VERSION 5.8 ;
BUSBITCHARS "[]" ;
DIVIDERCHAR "/" ;
UNITS
    DATABASE MICRONS 1000 ;
END UNITS

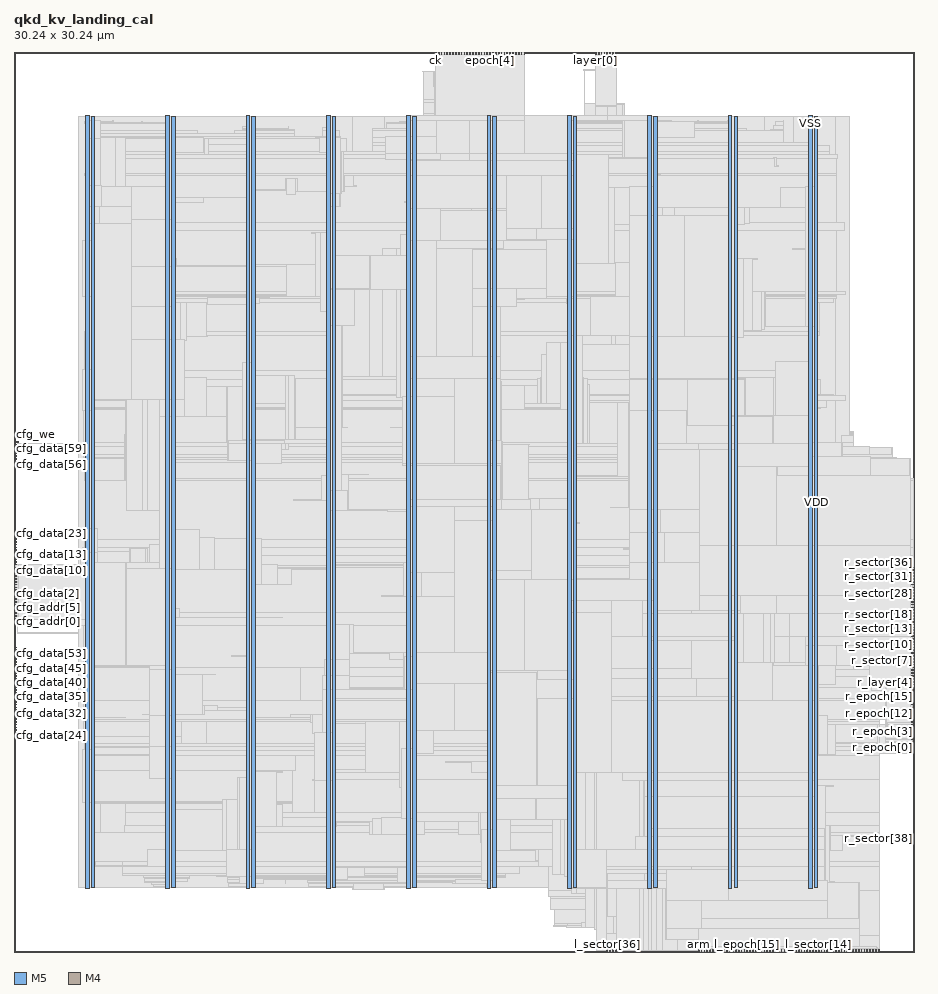
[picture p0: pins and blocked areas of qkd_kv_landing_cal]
MACRO qkd_kv_landing_cal
  FOREIGN qkd_kv_landing_cal 0 0 ;
  CLASS BLOCK ;
  SIZE 30.24 BY 30.24 ;
  PIN arm
    DIRECTION OUTPUT ;
    USE SIGNAL ;
    PORT
      LAYER M5 ;
        RECT  22.992 0 23.016 0.084 ;
    END
  END arm
  PIN cfg_addr[0]
    DIRECTION INPUT ;
    USE SIGNAL ;
    PORT
      LAYER M4 ;
        RECT  0 11.088 0.084 11.112 ;
    END
  END cfg_addr[0]
  PIN cfg_addr[1]
    DIRECTION INPUT ;
    USE SIGNAL ;
    PORT
      LAYER M4 ;
        RECT  0 11.184 0.084 11.208 ;
    END
  END cfg_addr[1]
  PIN cfg_addr[2]
    DIRECTION INPUT ;
    USE SIGNAL ;
    PORT
      LAYER M4 ;
        RECT  0 11.28 0.084 11.304 ;
    END
  END cfg_addr[2]
  PIN cfg_addr[3]
    DIRECTION INPUT ;
    USE SIGNAL ;
    PORT
      LAYER M4 ;
        RECT  0 11.376 0.084 11.4 ;
    END
  END cfg_addr[3]
  PIN cfg_addr[4]
    DIRECTION INPUT ;
    USE SIGNAL ;
    PORT
      LAYER M4 ;
        RECT  0 11.472 0.084 11.496 ;
    END
  END cfg_addr[4]
  PIN cfg_addr[5]
    DIRECTION INPUT ;
    USE SIGNAL ;
    PORT
      LAYER M4 ;
        RECT  0 11.568 0.084 11.592 ;
    END
  END cfg_addr[5]
  PIN cfg_addr[6]
    DIRECTION INPUT ;
    USE SIGNAL ;
    PORT
      LAYER M4 ;
        RECT  0 11.664 0.084 11.688 ;
    END
  END cfg_addr[6]
  PIN cfg_addr[7]
    DIRECTION INPUT ;
    USE SIGNAL ;
    PORT
      LAYER M4 ;
        RECT  0 11.76 0.084 11.784 ;
    END
  END cfg_addr[7]
  PIN cfg_data[0]
    DIRECTION INPUT ;
    USE SIGNAL ;
    PORT
      LAYER M4 ;
        RECT  0 11.856 0.084 11.88 ;
    END
  END cfg_data[0]
  PIN cfg_data[10]
    DIRECTION INPUT ;
    USE SIGNAL ;
    PORT
      LAYER M4 ;
        RECT  0 12.816 0.084 12.84 ;
    END
  END cfg_data[10]
  PIN cfg_data[11]
    DIRECTION INPUT ;
    USE SIGNAL ;
    PORT
      LAYER M4 ;
        RECT  0 12.912 0.084 12.936 ;
    END
  END cfg_data[11]
  PIN cfg_data[12]
    DIRECTION INPUT ;
    USE SIGNAL ;
    PORT
      LAYER M4 ;
        RECT  0 13.008 0.084 13.032 ;
    END
  END cfg_data[12]
  PIN cfg_data[13]
    DIRECTION INPUT ;
    USE SIGNAL ;
    PORT
      LAYER M4 ;
        RECT  0 13.104 0.084 13.128 ;
    END
  END cfg_data[13]
  PIN cfg_data[14]
    DIRECTION INPUT ;
    USE SIGNAL ;
    PORT
      LAYER M4 ;
        RECT  0 13.2 0.084 13.224 ;
    END
  END cfg_data[14]
  PIN cfg_data[15]
    DIRECTION INPUT ;
    USE SIGNAL ;
    PORT
      LAYER M4 ;
        RECT  0 13.296 0.084 13.32 ;
    END
  END cfg_data[15]
  PIN cfg_data[16]
    DIRECTION INPUT ;
    USE SIGNAL ;
    PORT
      LAYER M4 ;
        RECT  0 13.392 0.084 13.416 ;
    END
  END cfg_data[16]
  PIN cfg_data[17]
    DIRECTION INPUT ;
    USE SIGNAL ;
    PORT
      LAYER M4 ;
        RECT  0 13.488 0.084 13.512 ;
    END
  END cfg_data[17]
  PIN cfg_data[18]
    DIRECTION INPUT ;
    USE SIGNAL ;
    PORT
      LAYER M4 ;
        RECT  0 13.584 0.084 13.608 ;
    END
  END cfg_data[18]
  PIN cfg_data[19]
    DIRECTION INPUT ;
    USE SIGNAL ;
    PORT
      LAYER M4 ;
        RECT  0 13.68 0.084 13.704 ;
    END
  END cfg_data[19]
  PIN cfg_data[1]
    DIRECTION INPUT ;
    USE SIGNAL ;
    PORT
      LAYER M4 ;
        RECT  0 11.952 0.084 11.976 ;
    END
  END cfg_data[1]
  PIN cfg_data[20]
    DIRECTION INPUT ;
    USE SIGNAL ;
    PORT
      LAYER M4 ;
        RECT  0 13.776 0.084 13.8 ;
    END
  END cfg_data[20]
  PIN cfg_data[21]
    DIRECTION INPUT ;
    USE SIGNAL ;
    PORT
      LAYER M4 ;
        RECT  0 13.872 0.084 13.896 ;
    END
  END cfg_data[21]
  PIN cfg_data[22]
    DIRECTION INPUT ;
    USE SIGNAL ;
    PORT
      LAYER M4 ;
        RECT  0 13.968 0.084 13.992 ;
    END
  END cfg_data[22]
  PIN cfg_data[23]
    DIRECTION INPUT ;
    USE SIGNAL ;
    PORT
      LAYER M4 ;
        RECT  0 14.064 0.084 14.088 ;
    END
  END cfg_data[23]
  PIN cfg_data[24]
    DIRECTION INPUT ;
    USE SIGNAL ;
    PORT
      LAYER M4 ;
        RECT  0 7.248 0.084 7.272 ;
    END
  END cfg_data[24]
  PIN cfg_data[25]
    DIRECTION INPUT ;
    USE SIGNAL ;
    PORT
      LAYER M4 ;
        RECT  0 7.344 0.084 7.368 ;
    END
  END cfg_data[25]
  PIN cfg_data[26]
    DIRECTION INPUT ;
    USE SIGNAL ;
    PORT
      LAYER M4 ;
        RECT  0 7.44 0.084 7.464 ;
    END
  END cfg_data[26]
  PIN cfg_data[27]
    DIRECTION INPUT ;
    USE SIGNAL ;
    PORT
      LAYER M4 ;
        RECT  0 7.536 0.084 7.56 ;
    END
  END cfg_data[27]
  PIN cfg_data[28]
    DIRECTION INPUT ;
    USE SIGNAL ;
    PORT
      LAYER M4 ;
        RECT  0 7.632 0.084 7.656 ;
    END
  END cfg_data[28]
  PIN cfg_data[29]
    DIRECTION INPUT ;
    USE SIGNAL ;
    PORT
      LAYER M4 ;
        RECT  0 7.728 0.084 7.752 ;
    END
  END cfg_data[29]
  PIN cfg_data[2]
    DIRECTION INPUT ;
    USE SIGNAL ;
    PORT
      LAYER M4 ;
        RECT  0 12.048 0.084 12.072 ;
    END
  END cfg_data[2]
  PIN cfg_data[30]
    DIRECTION INPUT ;
    USE SIGNAL ;
    PORT
      LAYER M4 ;
        RECT  0 7.824 0.084 7.848 ;
    END
  END cfg_data[30]
  PIN cfg_data[31]
    DIRECTION INPUT ;
    USE SIGNAL ;
    PORT
      LAYER M4 ;
        RECT  0 7.92 0.084 7.944 ;
    END
  END cfg_data[31]
  PIN cfg_data[32]
    DIRECTION INPUT ;
    USE SIGNAL ;
    PORT
      LAYER M4 ;
        RECT  0 8.016 0.084 8.04 ;
    END
  END cfg_data[32]
  PIN cfg_data[33]
    DIRECTION INPUT ;
    USE SIGNAL ;
    PORT
      LAYER M4 ;
        RECT  0 8.112 0.084 8.136 ;
    END
  END cfg_data[33]
  PIN cfg_data[34]
    DIRECTION INPUT ;
    USE SIGNAL ;
    PORT
      LAYER M4 ;
        RECT  0 8.208 0.084 8.232 ;
    END
  END cfg_data[34]
  PIN cfg_data[35]
    DIRECTION INPUT ;
    USE SIGNAL ;
    PORT
      LAYER M4 ;
        RECT  0 8.304 0.084 8.328 ;
    END
  END cfg_data[35]
  PIN cfg_data[36]
    DIRECTION INPUT ;
    USE SIGNAL ;
    PORT
      LAYER M4 ;
        RECT  0 8.4 0.084 8.424 ;
    END
  END cfg_data[36]
  PIN cfg_data[37]
    DIRECTION INPUT ;
    USE SIGNAL ;
    PORT
      LAYER M4 ;
        RECT  0 8.496 0.084 8.52 ;
    END
  END cfg_data[37]
  PIN cfg_data[38]
    DIRECTION INPUT ;
    USE SIGNAL ;
    PORT
      LAYER M4 ;
        RECT  0 8.592 0.084 8.616 ;
    END
  END cfg_data[38]
  PIN cfg_data[39]
    DIRECTION INPUT ;
    USE SIGNAL ;
    PORT
      LAYER M4 ;
        RECT  0 8.688 0.084 8.712 ;
    END
  END cfg_data[39]
  PIN cfg_data[3]
    DIRECTION INPUT ;
    USE SIGNAL ;
    PORT
      LAYER M4 ;
        RECT  0 12.144 0.084 12.168 ;
    END
  END cfg_data[3]
  PIN cfg_data[40]
    DIRECTION INPUT ;
    USE SIGNAL ;
    PORT
      LAYER M4 ;
        RECT  0 8.784 0.084 8.808 ;
    END
  END cfg_data[40]
  PIN cfg_data[41]
    DIRECTION INPUT ;
    USE SIGNAL ;
    PORT
      LAYER M4 ;
        RECT  0 8.88 0.084 8.904 ;
    END
  END cfg_data[41]
  PIN cfg_data[42]
    DIRECTION INPUT ;
    USE SIGNAL ;
    PORT
      LAYER M4 ;
        RECT  0 8.976 0.084 9 ;
    END
  END cfg_data[42]
  PIN cfg_data[43]
    DIRECTION INPUT ;
    USE SIGNAL ;
    PORT
      LAYER M4 ;
        RECT  0 9.072 0.084 9.096 ;
    END
  END cfg_data[43]
  PIN cfg_data[44]
    DIRECTION INPUT ;
    USE SIGNAL ;
    PORT
      LAYER M4 ;
        RECT  0 9.168 0.084 9.192 ;
    END
  END cfg_data[44]
  PIN cfg_data[45]
    DIRECTION INPUT ;
    USE SIGNAL ;
    PORT
      LAYER M4 ;
        RECT  0 9.264 0.084 9.288 ;
    END
  END cfg_data[45]
  PIN cfg_data[46]
    DIRECTION INPUT ;
    USE SIGNAL ;
    PORT
      LAYER M4 ;
        RECT  0 9.36 0.084 9.384 ;
    END
  END cfg_data[46]
  PIN cfg_data[47]
    DIRECTION INPUT ;
    USE SIGNAL ;
    PORT
      LAYER M4 ;
        RECT  0 9.456 0.084 9.48 ;
    END
  END cfg_data[47]
  PIN cfg_data[48]
    DIRECTION INPUT ;
    USE SIGNAL ;
    PORT
      LAYER M4 ;
        RECT  0 9.552 0.084 9.576 ;
    END
  END cfg_data[48]
  PIN cfg_data[49]
    DIRECTION INPUT ;
    USE SIGNAL ;
    PORT
      LAYER M4 ;
        RECT  0 9.648 0.084 9.672 ;
    END
  END cfg_data[49]
  PIN cfg_data[4]
    DIRECTION INPUT ;
    USE SIGNAL ;
    PORT
      LAYER M4 ;
        RECT  0 12.24 0.084 12.264 ;
    END
  END cfg_data[4]
  PIN cfg_data[50]
    DIRECTION INPUT ;
    USE SIGNAL ;
    PORT
      LAYER M4 ;
        RECT  0 9.744 0.084 9.768 ;
    END
  END cfg_data[50]
  PIN cfg_data[51]
    DIRECTION INPUT ;
    USE SIGNAL ;
    PORT
      LAYER M4 ;
        RECT  0 9.84 0.084 9.864 ;
    END
  END cfg_data[51]
  PIN cfg_data[52]
    DIRECTION INPUT ;
    USE SIGNAL ;
    PORT
      LAYER M4 ;
        RECT  0 9.936 0.084 9.96 ;
    END
  END cfg_data[52]
  PIN cfg_data[53]
    DIRECTION INPUT ;
    USE SIGNAL ;
    PORT
      LAYER M4 ;
        RECT  0 10.032 0.084 10.056 ;
    END
  END cfg_data[53]
  PIN cfg_data[54]
    DIRECTION INPUT ;
    USE SIGNAL ;
    PORT
      LAYER M4 ;
        RECT  0 10.128 0.084 10.152 ;
    END
  END cfg_data[54]
  PIN cfg_data[55]
    DIRECTION INPUT ;
    USE SIGNAL ;
    PORT
      LAYER M4 ;
        RECT  0 10.224 0.084 10.248 ;
    END
  END cfg_data[55]
  PIN cfg_data[56]
    DIRECTION INPUT ;
    USE SIGNAL ;
    PORT
      LAYER M4 ;
        RECT  0 16.368 0.084 16.392 ;
    END
  END cfg_data[56]
  PIN cfg_data[57]
    DIRECTION INPUT ;
    USE SIGNAL ;
    PORT
      LAYER M4 ;
        RECT  0 16.464 0.084 16.488 ;
    END
  END cfg_data[57]
  PIN cfg_data[58]
    DIRECTION INPUT ;
    USE SIGNAL ;
    PORT
      LAYER M4 ;
        RECT  0 16.56 0.084 16.584 ;
    END
  END cfg_data[58]
  PIN cfg_data[59]
    DIRECTION INPUT ;
    USE SIGNAL ;
    PORT
      LAYER M4 ;
        RECT  0 16.656 0.084 16.68 ;
    END
  END cfg_data[59]
  PIN cfg_data[5]
    DIRECTION INPUT ;
    USE SIGNAL ;
    PORT
      LAYER M4 ;
        RECT  0 12.336 0.084 12.36 ;
    END
  END cfg_data[5]
  PIN cfg_data[60]
    DIRECTION INPUT ;
    USE SIGNAL ;
    PORT
      LAYER M4 ;
        RECT  0 16.752 0.084 16.776 ;
    END
  END cfg_data[60]
  PIN cfg_data[61]
    DIRECTION INPUT ;
    USE SIGNAL ;
    PORT
      LAYER M4 ;
        RECT  0 16.848 0.084 16.872 ;
    END
  END cfg_data[61]
  PIN cfg_data[62]
    DIRECTION INPUT ;
    USE SIGNAL ;
    PORT
      LAYER M4 ;
        RECT  0 16.944 0.084 16.968 ;
    END
  END cfg_data[62]
  PIN cfg_data[63]
    DIRECTION INPUT ;
    USE SIGNAL ;
    PORT
      LAYER M4 ;
        RECT  0 17.04 0.084 17.064 ;
    END
  END cfg_data[63]
  PIN cfg_data[6]
    DIRECTION INPUT ;
    USE SIGNAL ;
    PORT
      LAYER M4 ;
        RECT  0 12.432 0.084 12.456 ;
    END
  END cfg_data[6]
  PIN cfg_data[7]
    DIRECTION INPUT ;
    USE SIGNAL ;
    PORT
      LAYER M4 ;
        RECT  0 12.528 0.084 12.552 ;
    END
  END cfg_data[7]
  PIN cfg_data[8]
    DIRECTION INPUT ;
    USE SIGNAL ;
    PORT
      LAYER M4 ;
        RECT  0 12.624 0.084 12.648 ;
    END
  END cfg_data[8]
  PIN cfg_data[9]
    DIRECTION INPUT ;
    USE SIGNAL ;
    PORT
      LAYER M4 ;
        RECT  0 12.72 0.084 12.744 ;
    END
  END cfg_data[9]
  PIN cfg_we
    DIRECTION INPUT ;
    USE SIGNAL ;
    PORT
      LAYER M4 ;
        RECT  0 17.136 0.084 17.16 ;
    END
    PORT
      LAYER M4 ;
        RECT  0.06 17.136 0.137 17.16 ;
    END
  END cfg_we
  PIN ck
    DIRECTION INPUT ;
    USE SIGNAL ;
    PORT
      LAYER M5 ;
        RECT  14.16 30.156 14.184 30.24 ;
    END
  END ck
  PIN ctx_t[0]
    DIRECTION INPUT ;
    USE SIGNAL ;
    PORT
      LAYER M5 ;
        RECT  14.256 30.156 14.28 30.24 ;
    END
  END ctx_t[0]
  PIN ctx_t[10]
    DIRECTION INPUT ;
    USE SIGNAL ;
    PORT
      LAYER M5 ;
        RECT  15.216 30.156 15.24 30.24 ;
    END
  END ctx_t[10]
  PIN ctx_t[11]
    DIRECTION INPUT ;
    USE SIGNAL ;
    PORT
      LAYER M5 ;
        RECT  15.312 30.156 15.336 30.24 ;
    END
  END ctx_t[11]
  PIN ctx_t[12]
    DIRECTION INPUT ;
    USE SIGNAL ;
    PORT
      LAYER M5 ;
        RECT  15.408 30.156 15.432 30.24 ;
    END
  END ctx_t[12]
  PIN ctx_t[13]
    DIRECTION INPUT ;
    USE SIGNAL ;
    PORT
      LAYER M5 ;
        RECT  15.504 30.156 15.528 30.24 ;
    END
  END ctx_t[13]
  PIN ctx_t[1]
    DIRECTION INPUT ;
    USE SIGNAL ;
    PORT
      LAYER M5 ;
        RECT  14.352 30.156 14.376 30.24 ;
    END
  END ctx_t[1]
  PIN ctx_t[2]
    DIRECTION INPUT ;
    USE SIGNAL ;
    PORT
      LAYER M5 ;
        RECT  14.448 30.156 14.472 30.24 ;
    END
  END ctx_t[2]
  PIN ctx_t[3]
    DIRECTION INPUT ;
    USE SIGNAL ;
    PORT
      LAYER M5 ;
        RECT  14.544 30.156 14.568 30.24 ;
    END
  END ctx_t[3]
  PIN ctx_t[4]
    DIRECTION INPUT ;
    USE SIGNAL ;
    PORT
      LAYER M5 ;
        RECT  14.64 30.156 14.664 30.24 ;
    END
  END ctx_t[4]
  PIN ctx_t[5]
    DIRECTION INPUT ;
    USE SIGNAL ;
    PORT
      LAYER M5 ;
        RECT  14.736 30.156 14.76 30.24 ;
    END
  END ctx_t[5]
  PIN ctx_t[6]
    DIRECTION INPUT ;
    USE SIGNAL ;
    PORT
      LAYER M5 ;
        RECT  14.832 30.156 14.856 30.24 ;
    END
  END ctx_t[6]
  PIN ctx_t[7]
    DIRECTION INPUT ;
    USE SIGNAL ;
    PORT
      LAYER M5 ;
        RECT  14.928 30.156 14.952 30.24 ;
    END
  END ctx_t[7]
  PIN ctx_t[8]
    DIRECTION INPUT ;
    USE SIGNAL ;
    PORT
      LAYER M5 ;
        RECT  15.024 30.156 15.048 30.24 ;
    END
  END ctx_t[8]
  PIN ctx_t[9]
    DIRECTION INPUT ;
    USE SIGNAL ;
    PORT
      LAYER M5 ;
        RECT  15.12 30.156 15.144 30.24 ;
    END
  END ctx_t[9]
  PIN epoch[0]
    DIRECTION INPUT ;
    USE SIGNAL ;
    PORT
      LAYER M5 ;
        RECT  15.6 30.156 15.624 30.24 ;
    END
  END epoch[0]
  PIN epoch[10]
    DIRECTION INPUT ;
    USE SIGNAL ;
    PORT
      LAYER M5 ;
        RECT  16.56 30.156 16.584 30.24 ;
    END
  END epoch[10]
  PIN epoch[11]
    DIRECTION INPUT ;
    USE SIGNAL ;
    PORT
      LAYER M5 ;
        RECT  16.656 30.156 16.68 30.24 ;
    END
  END epoch[11]
  PIN epoch[12]
    DIRECTION INPUT ;
    USE SIGNAL ;
    PORT
      LAYER M5 ;
        RECT  16.752 30.156 16.776 30.24 ;
    END
  END epoch[12]
  PIN epoch[13]
    DIRECTION INPUT ;
    USE SIGNAL ;
    PORT
      LAYER M5 ;
        RECT  16.848 30.156 16.872 30.24 ;
    END
  END epoch[13]
  PIN epoch[14]
    DIRECTION INPUT ;
    USE SIGNAL ;
    PORT
      LAYER M5 ;
        RECT  16.944 30.156 16.968 30.24 ;
    END
  END epoch[14]
  PIN epoch[15]
    DIRECTION INPUT ;
    USE SIGNAL ;
    PORT
      LAYER M5 ;
        RECT  17.04 30.156 17.064 30.24 ;
    END
  END epoch[15]
  PIN epoch[1]
    DIRECTION INPUT ;
    USE SIGNAL ;
    PORT
      LAYER M5 ;
        RECT  15.696 30.156 15.72 30.24 ;
    END
  END epoch[1]
  PIN epoch[2]
    DIRECTION INPUT ;
    USE SIGNAL ;
    PORT
      LAYER M5 ;
        RECT  15.792 30.156 15.816 30.24 ;
    END
  END epoch[2]
  PIN epoch[3]
    DIRECTION INPUT ;
    USE SIGNAL ;
    PORT
      LAYER M5 ;
        RECT  15.888 30.156 15.912 30.24 ;
    END
  END epoch[3]
  PIN epoch[4]
    DIRECTION INPUT ;
    USE SIGNAL ;
    PORT
      LAYER M5 ;
        RECT  15.984 30.156 16.008 30.24 ;
    END
  END epoch[4]
  PIN epoch[5]
    DIRECTION INPUT ;
    USE SIGNAL ;
    PORT
      LAYER M5 ;
        RECT  16.08 30.156 16.104 30.24 ;
    END
  END epoch[5]
  PIN epoch[6]
    DIRECTION INPUT ;
    USE SIGNAL ;
    PORT
      LAYER M5 ;
        RECT  16.176 30.156 16.2 30.24 ;
    END
  END epoch[6]
  PIN epoch[7]
    DIRECTION INPUT ;
    USE SIGNAL ;
    PORT
      LAYER M5 ;
        RECT  16.272 30.156 16.296 30.24 ;
    END
  END epoch[7]
  PIN epoch[8]
    DIRECTION INPUT ;
    USE SIGNAL ;
    PORT
      LAYER M5 ;
        RECT  16.368 30.156 16.392 30.24 ;
    END
  END epoch[8]
  PIN epoch[9]
    DIRECTION INPUT ;
    USE SIGNAL ;
    PORT
      LAYER M5 ;
        RECT  16.464 30.156 16.488 30.24 ;
    END
  END epoch[9]
  PIN fault
    DIRECTION OUTPUT ;
    USE SIGNAL ;
    PORT
      LAYER M5 ;
        RECT  23.088 0 23.112 0.084 ;
    END
  END fault
  PIN kgo
    DIRECTION INPUT ;
    USE SIGNAL ;
    PORT
      LAYER M5 ;
        RECT  17.136 30.156 17.16 30.24 ;
    END
  END kgo
  PIN l_epoch[0]
    DIRECTION OUTPUT ;
    USE SIGNAL ;
    PORT
      LAYER M5 ;
        RECT  23.184 0 23.208 0.084 ;
    END
  END l_epoch[0]
  PIN l_epoch[10]
    DIRECTION OUTPUT ;
    USE SIGNAL ;
    PORT
      LAYER M5 ;
        RECT  24.144 0 24.168 0.084 ;
    END
  END l_epoch[10]
  PIN l_epoch[11]
    DIRECTION OUTPUT ;
    USE SIGNAL ;
    PORT
      LAYER M5 ;
        RECT  24.24 0 24.264 0.084 ;
    END
  END l_epoch[11]
  PIN l_epoch[12]
    DIRECTION OUTPUT ;
    USE SIGNAL ;
    PORT
      LAYER M5 ;
        RECT  24.336 0 24.36 0.084 ;
    END
  END l_epoch[12]
  PIN l_epoch[13]
    DIRECTION OUTPUT ;
    USE SIGNAL ;
    PORT
      LAYER M5 ;
        RECT  24.432 0 24.456 0.084 ;
    END
  END l_epoch[13]
  PIN l_epoch[14]
    DIRECTION OUTPUT ;
    USE SIGNAL ;
    PORT
      LAYER M5 ;
        RECT  24.528 0 24.552 0.084 ;
    END
  END l_epoch[14]
  PIN l_epoch[15]
    DIRECTION OUTPUT ;
    USE SIGNAL ;
    PORT
      LAYER M5 ;
        RECT  24.624 0 24.648 0.084 ;
    END
  END l_epoch[15]
  PIN l_epoch[1]
    DIRECTION OUTPUT ;
    USE SIGNAL ;
    PORT
      LAYER M5 ;
        RECT  23.28 0 23.304 0.084 ;
    END
  END l_epoch[1]
  PIN l_epoch[2]
    DIRECTION OUTPUT ;
    USE SIGNAL ;
    PORT
      LAYER M5 ;
        RECT  23.376 0 23.4 0.084 ;
    END
  END l_epoch[2]
  PIN l_epoch[3]
    DIRECTION OUTPUT ;
    USE SIGNAL ;
    PORT
      LAYER M5 ;
        RECT  23.472 0 23.496 0.084 ;
    END
  END l_epoch[3]
  PIN l_epoch[4]
    DIRECTION OUTPUT ;
    USE SIGNAL ;
    PORT
      LAYER M5 ;
        RECT  23.568 0 23.592 0.084 ;
    END
  END l_epoch[4]
  PIN l_epoch[5]
    DIRECTION OUTPUT ;
    USE SIGNAL ;
    PORT
      LAYER M5 ;
        RECT  23.664 0 23.688 0.084 ;
    END
  END l_epoch[5]
  PIN l_epoch[6]
    DIRECTION OUTPUT ;
    USE SIGNAL ;
    PORT
      LAYER M5 ;
        RECT  23.76 0 23.784 0.084 ;
    END
  END l_epoch[6]
  PIN l_epoch[7]
    DIRECTION OUTPUT ;
    USE SIGNAL ;
    PORT
      LAYER M5 ;
        RECT  23.856 0 23.88 0.084 ;
    END
  END l_epoch[7]
  PIN l_epoch[8]
    DIRECTION OUTPUT ;
    USE SIGNAL ;
    PORT
      LAYER M5 ;
        RECT  23.952 0 23.976 0.084 ;
    END
  END l_epoch[8]
  PIN l_epoch[9]
    DIRECTION OUTPUT ;
    USE SIGNAL ;
    PORT
      LAYER M5 ;
        RECT  24.048 0 24.072 0.084 ;
    END
  END l_epoch[9]
  PIN l_layer[0]
    DIRECTION OUTPUT ;
    USE SIGNAL ;
    PORT
      LAYER M5 ;
        RECT  24.72 0 24.744 0.084 ;
    END
  END l_layer[0]
  PIN l_layer[1]
    DIRECTION OUTPUT ;
    USE SIGNAL ;
    PORT
      LAYER M5 ;
        RECT  24.816 0 24.84 0.084 ;
    END
  END l_layer[1]
  PIN l_layer[2]
    DIRECTION OUTPUT ;
    USE SIGNAL ;
    PORT
      LAYER M5 ;
        RECT  24.912 0 24.936 0.084 ;
    END
  END l_layer[2]
  PIN l_layer[3]
    DIRECTION OUTPUT ;
    USE SIGNAL ;
    PORT
      LAYER M5 ;
        RECT  25.008 0 25.032 0.084 ;
    END
  END l_layer[3]
  PIN l_layer[4]
    DIRECTION OUTPUT ;
    USE SIGNAL ;
    PORT
      LAYER M5 ;
        RECT  25.104 0 25.128 0.084 ;
    END
  END l_layer[4]
  PIN l_layer[5]
    DIRECTION OUTPUT ;
    USE SIGNAL ;
    PORT
      LAYER M5 ;
        RECT  25.2 0 25.224 0.084 ;
    END
  END l_layer[5]
  PIN l_put[0]
    DIRECTION OUTPUT ;
    USE SIGNAL ;
    PORT
      LAYER M5 ;
        RECT  25.296 0 25.32 0.084 ;
    END
  END l_put[0]
  PIN l_put[1]
    DIRECTION OUTPUT ;
    USE SIGNAL ;
    PORT
      LAYER M5 ;
        RECT  25.392 0 25.416 0.084 ;
    END
  END l_put[1]
  PIN l_put[2]
    DIRECTION OUTPUT ;
    USE SIGNAL ;
    PORT
      LAYER M5 ;
        RECT  25.488 0 25.512 0.084 ;
    END
  END l_put[2]
  PIN l_put[3]
    DIRECTION OUTPUT ;
    USE SIGNAL ;
    PORT
      LAYER M5 ;
        RECT  25.584 0 25.608 0.084 ;
    END
  END l_put[3]
  PIN l_sector[0]
    DIRECTION OUTPUT ;
    USE SIGNAL ;
    PORT
      LAYER M5 ;
        RECT  25.68 0 25.704 0.084 ;
    END
  END l_sector[0]
  PIN l_sector[10]
    DIRECTION OUTPUT ;
    USE SIGNAL ;
    PORT
      LAYER M5 ;
        RECT  26.64 0 26.664 0.084 ;
    END
  END l_sector[10]
  PIN l_sector[11]
    DIRECTION OUTPUT ;
    USE SIGNAL ;
    PORT
      LAYER M5 ;
        RECT  26.736 0 26.76 0.084 ;
    END
  END l_sector[11]
  PIN l_sector[12]
    DIRECTION OUTPUT ;
    USE SIGNAL ;
    PORT
      LAYER M5 ;
        RECT  26.832 0 26.856 0.084 ;
    END
  END l_sector[12]
  PIN l_sector[13]
    DIRECTION OUTPUT ;
    USE SIGNAL ;
    PORT
      LAYER M5 ;
        RECT  26.928 0 26.952 0.084 ;
    END
  END l_sector[13]
  PIN l_sector[14]
    DIRECTION OUTPUT ;
    USE SIGNAL ;
    PORT
      LAYER M5 ;
        RECT  27.024 0 27.048 0.084 ;
    END
  END l_sector[14]
  PIN l_sector[15]
    DIRECTION OUTPUT ;
    USE SIGNAL ;
    PORT
      LAYER M5 ;
        RECT  27.12 0 27.144 0.084 ;
    END
  END l_sector[15]
  PIN l_sector[16]
    DIRECTION OUTPUT ;
    USE SIGNAL ;
    PORT
      LAYER M5 ;
        RECT  27.216 0 27.24 0.084 ;
    END
  END l_sector[16]
  PIN l_sector[17]
    DIRECTION OUTPUT ;
    USE SIGNAL ;
    PORT
      LAYER M5 ;
        RECT  27.312 0 27.336 0.084 ;
    END
  END l_sector[17]
  PIN l_sector[18]
    DIRECTION OUTPUT ;
    USE SIGNAL ;
    PORT
      LAYER M5 ;
        RECT  27.408 0 27.432 0.084 ;
    END
  END l_sector[18]
  PIN l_sector[19]
    DIRECTION OUTPUT ;
    USE SIGNAL ;
    PORT
      LAYER M5 ;
        RECT  27.504 0 27.528 0.084 ;
    END
  END l_sector[19]
  PIN l_sector[1]
    DIRECTION OUTPUT ;
    USE SIGNAL ;
    PORT
      LAYER M5 ;
        RECT  25.776 0 25.8 0.084 ;
    END
  END l_sector[1]
  PIN l_sector[20]
    DIRECTION OUTPUT ;
    USE SIGNAL ;
    PORT
      LAYER M5 ;
        RECT  27.6 0 27.624 0.084 ;
    END
  END l_sector[20]
  PIN l_sector[21]
    DIRECTION OUTPUT ;
    USE SIGNAL ;
    PORT
      LAYER M5 ;
        RECT  27.696 0 27.72 0.084 ;
    END
  END l_sector[21]
  PIN l_sector[22]
    DIRECTION OUTPUT ;
    USE SIGNAL ;
    PORT
      LAYER M5 ;
        RECT  27.792 0 27.816 0.084 ;
    END
  END l_sector[22]
  PIN l_sector[23]
    DIRECTION OUTPUT ;
    USE SIGNAL ;
    PORT
      LAYER M5 ;
        RECT  27.888 0 27.912 0.084 ;
    END
  END l_sector[23]
  PIN l_sector[24]
    DIRECTION OUTPUT ;
    USE SIGNAL ;
    PORT
      LAYER M5 ;
        RECT  27.984 0 28.008 0.084 ;
    END
  END l_sector[24]
  PIN l_sector[25]
    DIRECTION OUTPUT ;
    USE SIGNAL ;
    PORT
      LAYER M5 ;
        RECT  28.08 0 28.104 0.084 ;
    END
  END l_sector[25]
  PIN l_sector[26]
    DIRECTION OUTPUT ;
    USE SIGNAL ;
    PORT
      LAYER M5 ;
        RECT  28.176 0 28.2 0.084 ;
    END
  END l_sector[26]
  PIN l_sector[27]
    DIRECTION OUTPUT ;
    USE SIGNAL ;
    PORT
      LAYER M5 ;
        RECT  28.272 0 28.296 0.084 ;
    END
  END l_sector[27]
  PIN l_sector[28]
    DIRECTION OUTPUT ;
    USE SIGNAL ;
    PORT
      LAYER M5 ;
        RECT  28.368 0 28.392 0.084 ;
    END
  END l_sector[28]
  PIN l_sector[29]
    DIRECTION OUTPUT ;
    USE SIGNAL ;
    PORT
      LAYER M5 ;
        RECT  28.464 0 28.488 0.084 ;
    END
  END l_sector[29]
  PIN l_sector[2]
    DIRECTION OUTPUT ;
    USE SIGNAL ;
    PORT
      LAYER M5 ;
        RECT  25.872 0 25.896 0.084 ;
    END
  END l_sector[2]
  PIN l_sector[30]
    DIRECTION OUTPUT ;
    USE SIGNAL ;
    PORT
      LAYER M5 ;
        RECT  28.56 0 28.584 0.084 ;
    END
  END l_sector[30]
  PIN l_sector[31]
    DIRECTION OUTPUT ;
    USE SIGNAL ;
    PORT
      LAYER M5 ;
        RECT  28.656 0 28.68 0.084 ;
    END
  END l_sector[31]
  PIN l_sector[32]
    DIRECTION OUTPUT ;
    USE SIGNAL ;
    PORT
      LAYER M5 ;
        RECT  28.752 0 28.776 0.084 ;
    END
  END l_sector[32]
  PIN l_sector[33]
    DIRECTION OUTPUT ;
    USE SIGNAL ;
    PORT
      LAYER M5 ;
        RECT  28.848 0 28.872 0.084 ;
    END
  END l_sector[33]
  PIN l_sector[34]
    DIRECTION OUTPUT ;
    USE SIGNAL ;
    PORT
      LAYER M5 ;
        RECT  28.944 0 28.968 0.084 ;
    END
  END l_sector[34]
  PIN l_sector[35]
    DIRECTION OUTPUT ;
    USE SIGNAL ;
    PORT
      LAYER M5 ;
        RECT  29.04 0 29.064 0.084 ;
    END
  END l_sector[35]
  PIN l_sector[36]
    DIRECTION OUTPUT ;
    USE SIGNAL ;
    PORT
      LAYER M5 ;
        RECT  19.92 0 19.944 0.084 ;
    END
  END l_sector[36]
  PIN l_sector[37]
    DIRECTION OUTPUT ;
    USE SIGNAL ;
    PORT
      LAYER M5 ;
        RECT  20.016 0 20.04 0.084 ;
    END
  END l_sector[37]
  PIN l_sector[38]
    DIRECTION OUTPUT ;
    USE SIGNAL ;
    PORT
      LAYER M5 ;
        RECT  20.112 0 20.136 0.084 ;
    END
  END l_sector[38]
  PIN l_sector[39]
    DIRECTION OUTPUT ;
    USE SIGNAL ;
    PORT
      LAYER M5 ;
        RECT  20.208 0 20.232 0.084 ;
    END
  END l_sector[39]
  PIN l_sector[3]
    DIRECTION OUTPUT ;
    USE SIGNAL ;
    PORT
      LAYER M5 ;
        RECT  25.968 0 25.992 0.084 ;
    END
  END l_sector[3]
  PIN l_sector[4]
    DIRECTION OUTPUT ;
    USE SIGNAL ;
    PORT
      LAYER M5 ;
        RECT  26.064 0 26.088 0.084 ;
    END
  END l_sector[4]
  PIN l_sector[5]
    DIRECTION OUTPUT ;
    USE SIGNAL ;
    PORT
      LAYER M5 ;
        RECT  26.16 0 26.184 0.084 ;
    END
  END l_sector[5]
  PIN l_sector[6]
    DIRECTION OUTPUT ;
    USE SIGNAL ;
    PORT
      LAYER M5 ;
        RECT  26.256 0 26.28 0.084 ;
    END
  END l_sector[6]
  PIN l_sector[7]
    DIRECTION OUTPUT ;
    USE SIGNAL ;
    PORT
      LAYER M5 ;
        RECT  26.352 0 26.376 0.084 ;
    END
  END l_sector[7]
  PIN l_sector[8]
    DIRECTION OUTPUT ;
    USE SIGNAL ;
    PORT
      LAYER M5 ;
        RECT  26.448 0 26.472 0.084 ;
    END
  END l_sector[8]
  PIN l_sector[9]
    DIRECTION OUTPUT ;
    USE SIGNAL ;
    PORT
      LAYER M5 ;
        RECT  26.544 0 26.568 0.084 ;
    END
  END l_sector[9]
  PIN layer[0]
    DIRECTION INPUT ;
    USE SIGNAL ;
    PORT
      LAYER M5 ;
        RECT  19.536 30.156 19.56 30.24 ;
    END
  END layer[0]
  PIN layer[1]
    DIRECTION INPUT ;
    USE SIGNAL ;
    PORT
      LAYER M5 ;
        RECT  19.632 30.156 19.656 30.24 ;
    END
  END layer[1]
  PIN layer[2]
    DIRECTION INPUT ;
    USE SIGNAL ;
    PORT
      LAYER M5 ;
        RECT  19.728 30.156 19.752 30.24 ;
    END
  END layer[2]
  PIN layer[3]
    DIRECTION INPUT ;
    USE SIGNAL ;
    PORT
      LAYER M5 ;
        RECT  19.824 30.156 19.848 30.24 ;
    END
  END layer[3]
  PIN layer[4]
    DIRECTION INPUT ;
    USE SIGNAL ;
    PORT
      LAYER M5 ;
        RECT  19.92 30.156 19.944 30.24 ;
    END
  END layer[4]
  PIN layer[5]
    DIRECTION INPUT ;
    USE SIGNAL ;
    PORT
      LAYER M5 ;
        RECT  20.016 30.156 20.04 30.24 ;
    END
  END layer[5]
  PIN r_epoch[0]
    DIRECTION OUTPUT ;
    USE SIGNAL ;
    PORT
      LAYER M4 ;
        RECT  30.156 6.864 30.24 6.888 ;
    END
  END r_epoch[0]
  PIN r_epoch[10]
    DIRECTION OUTPUT ;
    USE SIGNAL ;
    PORT
      LAYER M4 ;
        RECT  30.156 7.824 30.24 7.848 ;
    END
  END r_epoch[10]
  PIN r_epoch[11]
    DIRECTION OUTPUT ;
    USE SIGNAL ;
    PORT
      LAYER M4 ;
        RECT  30.156 7.92 30.24 7.944 ;
    END
  END r_epoch[11]
  PIN r_epoch[12]
    DIRECTION OUTPUT ;
    USE SIGNAL ;
    PORT
      LAYER M4 ;
        RECT  30.156 8.016 30.24 8.04 ;
    END
  END r_epoch[12]
  PIN r_epoch[13]
    DIRECTION OUTPUT ;
    USE SIGNAL ;
    PORT
      LAYER M4 ;
        RECT  30.156 8.112 30.24 8.136 ;
    END
  END r_epoch[13]
  PIN r_epoch[14]
    DIRECTION OUTPUT ;
    USE SIGNAL ;
    PORT
      LAYER M4 ;
        RECT  30.156 8.208 30.24 8.232 ;
    END
  END r_epoch[14]
  PIN r_epoch[15]
    DIRECTION OUTPUT ;
    USE SIGNAL ;
    PORT
      LAYER M4 ;
        RECT  30.156 8.304 30.24 8.328 ;
    END
  END r_epoch[15]
  PIN r_epoch[1]
    DIRECTION OUTPUT ;
    USE SIGNAL ;
    PORT
      LAYER M4 ;
        RECT  30.156 6.96 30.24 6.984 ;
    END
  END r_epoch[1]
  PIN r_epoch[2]
    DIRECTION OUTPUT ;
    USE SIGNAL ;
    PORT
      LAYER M4 ;
        RECT  30.156 7.056 30.24 7.08 ;
    END
  END r_epoch[2]
  PIN r_epoch[3]
    DIRECTION OUTPUT ;
    USE SIGNAL ;
    PORT
      LAYER M4 ;
        RECT  30.156 7.152 30.24 7.176 ;
    END
  END r_epoch[3]
  PIN r_epoch[4]
    DIRECTION OUTPUT ;
    USE SIGNAL ;
    PORT
      LAYER M4 ;
        RECT  30.156 7.248 30.24 7.272 ;
    END
  END r_epoch[4]
  PIN r_epoch[5]
    DIRECTION OUTPUT ;
    USE SIGNAL ;
    PORT
      LAYER M4 ;
        RECT  30.156 7.344 30.24 7.368 ;
    END
  END r_epoch[5]
  PIN r_epoch[6]
    DIRECTION OUTPUT ;
    USE SIGNAL ;
    PORT
      LAYER M4 ;
        RECT  30.156 7.44 30.24 7.464 ;
    END
  END r_epoch[6]
  PIN r_epoch[7]
    DIRECTION OUTPUT ;
    USE SIGNAL ;
    PORT
      LAYER M4 ;
        RECT  30.156 7.536 30.24 7.56 ;
    END
  END r_epoch[7]
  PIN r_epoch[8]
    DIRECTION OUTPUT ;
    USE SIGNAL ;
    PORT
      LAYER M4 ;
        RECT  30.156 7.632 30.24 7.656 ;
    END
  END r_epoch[8]
  PIN r_epoch[9]
    DIRECTION OUTPUT ;
    USE SIGNAL ;
    PORT
      LAYER M4 ;
        RECT  30.156 7.728 30.24 7.752 ;
    END
  END r_epoch[9]
  PIN r_layer[0]
    DIRECTION OUTPUT ;
    USE SIGNAL ;
    PORT
      LAYER M4 ;
        RECT  30.156 8.4 30.24 8.424 ;
    END
  END r_layer[0]
  PIN r_layer[1]
    DIRECTION OUTPUT ;
    USE SIGNAL ;
    PORT
      LAYER M4 ;
        RECT  30.156 8.496 30.24 8.52 ;
    END
  END r_layer[1]
  PIN r_layer[2]
    DIRECTION OUTPUT ;
    USE SIGNAL ;
    PORT
      LAYER M4 ;
        RECT  30.156 8.592 30.24 8.616 ;
    END
  END r_layer[2]
  PIN r_layer[3]
    DIRECTION OUTPUT ;
    USE SIGNAL ;
    PORT
      LAYER M4 ;
        RECT  30.156 8.688 30.24 8.712 ;
    END
  END r_layer[3]
  PIN r_layer[4]
    DIRECTION OUTPUT ;
    USE SIGNAL ;
    PORT
      LAYER M4 ;
        RECT  30.156 8.784 30.24 8.808 ;
    END
  END r_layer[4]
  PIN r_layer[5]
    DIRECTION OUTPUT ;
    USE SIGNAL ;
    PORT
      LAYER M4 ;
        RECT  30.156 8.88 30.24 8.904 ;
    END
  END r_layer[5]
  PIN r_put[0]
    DIRECTION OUTPUT ;
    USE SIGNAL ;
    PORT
      LAYER M4 ;
        RECT  30.156 8.976 30.24 9 ;
    END
  END r_put[0]
  PIN r_put[1]
    DIRECTION OUTPUT ;
    USE SIGNAL ;
    PORT
      LAYER M4 ;
        RECT  30.156 9.072 30.24 9.096 ;
    END
  END r_put[1]
  PIN r_put[2]
    DIRECTION OUTPUT ;
    USE SIGNAL ;
    PORT
      LAYER M4 ;
        RECT  30.156 9.168 30.24 9.192 ;
    END
  END r_put[2]
  PIN r_put[3]
    DIRECTION OUTPUT ;
    USE SIGNAL ;
    PORT
      LAYER M4 ;
        RECT  30.156 9.264 30.24 9.288 ;
    END
  END r_put[3]
  PIN r_sector[0]
    DIRECTION OUTPUT ;
    USE SIGNAL ;
    PORT
      LAYER M4 ;
        RECT  30.156 9.36 30.24 9.384 ;
    END
  END r_sector[0]
  PIN r_sector[10]
    DIRECTION OUTPUT ;
    USE SIGNAL ;
    PORT
      LAYER M4 ;
        RECT  30.156 10.32 30.24 10.344 ;
    END
  END r_sector[10]
  PIN r_sector[11]
    DIRECTION OUTPUT ;
    USE SIGNAL ;
    PORT
      LAYER M4 ;
        RECT  30.156 10.416 30.24 10.44 ;
    END
  END r_sector[11]
  PIN r_sector[12]
    DIRECTION OUTPUT ;
    USE SIGNAL ;
    PORT
      LAYER M4 ;
        RECT  30.156 10.512 30.24 10.536 ;
    END
  END r_sector[12]
  PIN r_sector[13]
    DIRECTION OUTPUT ;
    USE SIGNAL ;
    PORT
      LAYER M4 ;
        RECT  30.156 10.608 30.24 10.632 ;
    END
  END r_sector[13]
  PIN r_sector[14]
    DIRECTION OUTPUT ;
    USE SIGNAL ;
    PORT
      LAYER M4 ;
        RECT  30.156 10.704 30.24 10.728 ;
    END
  END r_sector[14]
  PIN r_sector[15]
    DIRECTION OUTPUT ;
    USE SIGNAL ;
    PORT
      LAYER M4 ;
        RECT  30.156 10.8 30.24 10.824 ;
    END
  END r_sector[15]
  PIN r_sector[16]
    DIRECTION OUTPUT ;
    USE SIGNAL ;
    PORT
      LAYER M4 ;
        RECT  30.156 10.896 30.24 10.92 ;
    END
  END r_sector[16]
  PIN r_sector[17]
    DIRECTION OUTPUT ;
    USE SIGNAL ;
    PORT
      LAYER M4 ;
        RECT  30.156 10.992 30.24 11.016 ;
    END
  END r_sector[17]
  PIN r_sector[18]
    DIRECTION OUTPUT ;
    USE SIGNAL ;
    PORT
      LAYER M4 ;
        RECT  30.156 11.088 30.24 11.112 ;
    END
  END r_sector[18]
  PIN r_sector[19]
    DIRECTION OUTPUT ;
    USE SIGNAL ;
    PORT
      LAYER M4 ;
        RECT  30.156 11.184 30.24 11.208 ;
    END
  END r_sector[19]
  PIN r_sector[1]
    DIRECTION OUTPUT ;
    USE SIGNAL ;
    PORT
      LAYER M4 ;
        RECT  30.156 9.456 30.24 9.48 ;
    END
  END r_sector[1]
  PIN r_sector[20]
    DIRECTION OUTPUT ;
    USE SIGNAL ;
    PORT
      LAYER M4 ;
        RECT  30.156 11.28 30.24 11.304 ;
    END
  END r_sector[20]
  PIN r_sector[21]
    DIRECTION OUTPUT ;
    USE SIGNAL ;
    PORT
      LAYER M4 ;
        RECT  30.156 11.376 30.24 11.4 ;
    END
  END r_sector[21]
  PIN r_sector[22]
    DIRECTION OUTPUT ;
    USE SIGNAL ;
    PORT
      LAYER M4 ;
        RECT  30.156 11.472 30.24 11.496 ;
    END
  END r_sector[22]
  PIN r_sector[23]
    DIRECTION OUTPUT ;
    USE SIGNAL ;
    PORT
      LAYER M4 ;
        RECT  30.156 11.568 30.24 11.592 ;
    END
  END r_sector[23]
  PIN r_sector[24]
    DIRECTION OUTPUT ;
    USE SIGNAL ;
    PORT
      LAYER M4 ;
        RECT  30.156 11.664 30.24 11.688 ;
    END
  END r_sector[24]
  PIN r_sector[25]
    DIRECTION OUTPUT ;
    USE SIGNAL ;
    PORT
      LAYER M4 ;
        RECT  30.156 11.76 30.24 11.784 ;
    END
  END r_sector[25]
  PIN r_sector[26]
    DIRECTION OUTPUT ;
    USE SIGNAL ;
    PORT
      LAYER M4 ;
        RECT  30.156 11.856 30.24 11.88 ;
    END
  END r_sector[26]
  PIN r_sector[27]
    DIRECTION OUTPUT ;
    USE SIGNAL ;
    PORT
      LAYER M4 ;
        RECT  30.156 11.952 30.24 11.976 ;
    END
  END r_sector[27]
  PIN r_sector[28]
    DIRECTION OUTPUT ;
    USE SIGNAL ;
    PORT
      LAYER M4 ;
        RECT  30.156 12.048 30.24 12.072 ;
    END
  END r_sector[28]
  PIN r_sector[29]
    DIRECTION OUTPUT ;
    USE SIGNAL ;
    PORT
      LAYER M4 ;
        RECT  30.156 12.144 30.24 12.168 ;
    END
  END r_sector[29]
  PIN r_sector[2]
    DIRECTION OUTPUT ;
    USE SIGNAL ;
    PORT
      LAYER M4 ;
        RECT  30.156 9.552 30.24 9.576 ;
    END
  END r_sector[2]
  PIN r_sector[30]
    DIRECTION OUTPUT ;
    USE SIGNAL ;
    PORT
      LAYER M4 ;
        RECT  30.156 12.24 30.24 12.264 ;
    END
  END r_sector[30]
  PIN r_sector[31]
    DIRECTION OUTPUT ;
    USE SIGNAL ;
    PORT
      LAYER M4 ;
        RECT  30.156 12.336 30.24 12.36 ;
    END
  END r_sector[31]
  PIN r_sector[32]
    DIRECTION OUTPUT ;
    USE SIGNAL ;
    PORT
      LAYER M4 ;
        RECT  30.156 12.432 30.24 12.456 ;
    END
  END r_sector[32]
  PIN r_sector[33]
    DIRECTION OUTPUT ;
    USE SIGNAL ;
    PORT
      LAYER M4 ;
        RECT  30.156 12.528 30.24 12.552 ;
    END
  END r_sector[33]
  PIN r_sector[34]
    DIRECTION OUTPUT ;
    USE SIGNAL ;
    PORT
      LAYER M4 ;
        RECT  30.156 12.624 30.24 12.648 ;
    END
  END r_sector[34]
  PIN r_sector[35]
    DIRECTION OUTPUT ;
    USE SIGNAL ;
    PORT
      LAYER M4 ;
        RECT  30.156 12.72 30.24 12.744 ;
    END
  END r_sector[35]
  PIN r_sector[36]
    DIRECTION OUTPUT ;
    USE SIGNAL ;
    PORT
      LAYER M4 ;
        RECT  30.156 12.816 30.24 12.84 ;
    END
  END r_sector[36]
  PIN r_sector[37]
    DIRECTION OUTPUT ;
    USE SIGNAL ;
    PORT
      LAYER M4 ;
        RECT  30.156 12.912 30.24 12.936 ;
    END
  END r_sector[37]
  PIN r_sector[38]
    DIRECTION OUTPUT ;
    USE SIGNAL ;
    PORT
      LAYER M4 ;
        RECT  30.156 3.792 30.24 3.816 ;
    END
  END r_sector[38]
  PIN r_sector[39]
    DIRECTION OUTPUT ;
    USE SIGNAL ;
    PORT
      LAYER M4 ;
        RECT  30.156 3.888 30.24 3.912 ;
    END
  END r_sector[39]
  PIN r_sector[3]
    DIRECTION OUTPUT ;
    USE SIGNAL ;
    PORT
      LAYER M4 ;
        RECT  30.156 9.648 30.24 9.672 ;
    END
  END r_sector[3]
  PIN r_sector[4]
    DIRECTION OUTPUT ;
    USE SIGNAL ;
    PORT
      LAYER M4 ;
        RECT  30.156 9.744 30.24 9.768 ;
    END
  END r_sector[4]
  PIN r_sector[5]
    DIRECTION OUTPUT ;
    USE SIGNAL ;
    PORT
      LAYER M4 ;
        RECT  30.156 9.84 30.24 9.864 ;
    END
  END r_sector[5]
  PIN r_sector[6]
    DIRECTION OUTPUT ;
    USE SIGNAL ;
    PORT
      LAYER M4 ;
        RECT  30.156 9.936 30.24 9.96 ;
    END
  END r_sector[6]
  PIN r_sector[7]
    DIRECTION OUTPUT ;
    USE SIGNAL ;
    PORT
      LAYER M4 ;
        RECT  30.156 10.032 30.24 10.056 ;
    END
  END r_sector[7]
  PIN r_sector[8]
    DIRECTION OUTPUT ;
    USE SIGNAL ;
    PORT
      LAYER M4 ;
        RECT  30.156 10.128 30.24 10.152 ;
    END
  END r_sector[8]
  PIN r_sector[9]
    DIRECTION OUTPUT ;
    USE SIGNAL ;
    PORT
      LAYER M4 ;
        RECT  30.156 10.224 30.24 10.248 ;
    END
  END r_sector[9]
  PIN rst_n
    DIRECTION INPUT ;
    USE SIGNAL ;
    PORT
      LAYER M5 ;
        RECT  20.112 30.156 20.136 30.24 ;
    END
  END rst_n
  PIN vgo
    DIRECTION INPUT ;
    USE SIGNAL ;
    PORT
      LAYER M5 ;
        RECT  20.208 30.156 20.232 30.24 ;
    END
  END vgo
  PIN VDD
    DIRECTION INOUT ;
    USE POWER ;
    PORT
      LAYER M5 ;
        RECT  26.892 2.151 27.012 28.089 ;
        RECT  24.192 2.151 24.312 28.089 ;
        RECT  21.492 2.151 21.612 28.089 ;
        RECT  18.792 2.151 18.912 28.089 ;
        RECT  16.092 2.151 16.212 28.089 ;
        RECT  13.392 2.151 13.512 28.089 ;
        RECT  10.692 2.151 10.812 28.089 ;
        RECT  7.992 2.151 8.112 28.089 ;
        RECT  5.292 2.151 5.412 28.089 ;
        RECT  2.592 2.151 2.712 28.089 ;
    END
  END VDD
  PIN VSS
    DIRECTION INOUT ;
    USE GROUND ;
    PORT
      LAYER M5 ;
        RECT  26.7 2.137 26.82 28.103 ;
        RECT  24 2.137 24.12 28.103 ;
        RECT  21.3 2.137 21.42 28.103 ;
        RECT  18.6 2.137 18.72 28.103 ;
        RECT  15.9 2.137 16.02 28.103 ;
        RECT  13.2 2.137 13.32 28.103 ;
        RECT  10.5 2.137 10.62 28.103 ;
        RECT  7.8 2.137 7.92 28.103 ;
        RECT  5.1 2.137 5.22 28.103 ;
        RECT  2.4 2.137 2.52 28.103 ;
    END
  END VSS
  # OT_OBS_CLOSED layer=M5 d_um=1.536 added=87
  OBS
    LAYER RVTN ;
     RECT  2.16 2.16 28.08 2.295 ;
     RECT  2.16 2.565 28.08 2.835 ;
     RECT  2.16 3.105 28.08 3.375 ;
     RECT  2.16 3.645 28.08 3.915 ;
     RECT  2.16 4.185 28.08 4.455 ;
     RECT  2.16 4.725 28.08 4.995 ;
     RECT  2.16 5.265 28.08 5.535 ;
     RECT  2.16 5.805 28.08 6.075 ;
     RECT  2.16 6.345 28.08 6.615 ;
     RECT  2.16 6.885 28.08 7.155 ;
     RECT  2.16 7.425 28.08 7.695 ;
     RECT  2.16 7.965 28.08 8.235 ;
     RECT  2.16 8.505 28.08 8.775 ;
     RECT  2.16 9.045 28.08 9.315 ;
     RECT  2.16 9.585 28.08 9.855 ;
     RECT  2.16 10.125 28.08 10.395 ;
     RECT  2.16 10.665 28.08 10.935 ;
     RECT  2.16 11.205 28.08 11.475 ;
     RECT  2.16 11.745 28.08 12.015 ;
     RECT  2.16 12.285 28.08 12.555 ;
     RECT  2.16 12.825 28.08 13.095 ;
     RECT  2.16 13.365 28.08 13.635 ;
     RECT  2.16 13.905 28.08 14.175 ;
     RECT  2.16 14.445 28.08 14.715 ;
     RECT  2.16 14.985 28.08 15.255 ;
     RECT  2.16 15.525 28.08 15.795 ;
     RECT  2.16 16.065 28.08 16.335 ;
     RECT  2.16 16.605 28.08 16.875 ;
     RECT  2.16 17.145 28.08 17.415 ;
     RECT  2.16 17.685 28.08 17.955 ;
     RECT  2.16 18.225 28.08 18.495 ;
     RECT  2.16 18.765 28.08 19.035 ;
     RECT  2.16 19.305 28.08 19.575 ;
     RECT  2.16 19.845 28.08 20.115 ;
     RECT  2.16 20.385 28.08 20.655 ;
     RECT  2.16 20.925 28.08 21.195 ;
     RECT  2.16 21.465 28.08 21.735 ;
     RECT  2.16 22.005 28.08 22.275 ;
     RECT  2.16 22.545 28.08 22.815 ;
     RECT  2.16 23.085 28.08 23.355 ;
     RECT  2.16 23.625 28.08 23.895 ;
     RECT  2.16 24.165 28.08 24.435 ;
     RECT  2.16 24.705 28.08 24.975 ;
     RECT  2.16 25.245 28.08 25.515 ;
     RECT  2.16 25.785 28.08 26.055 ;
     RECT  2.16 26.325 28.08 26.595 ;
     RECT  2.16 26.865 28.08 27.135 ;
     RECT  2.16 27.405 28.08 27.675 ;
     RECT  2.16 27.945 28.08 28.08 ;
    LAYER RVTP ;
     RECT  2.16 2.295 28.08 2.565 ;
     RECT  2.16 2.835 28.08 3.105 ;
     RECT  2.16 3.375 28.08 3.645 ;
     RECT  2.16 3.915 28.08 4.185 ;
     RECT  2.16 4.455 28.08 4.725 ;
     RECT  2.16 4.995 28.08 5.265 ;
     RECT  2.16 5.535 28.08 5.805 ;
     RECT  2.16 6.075 28.08 6.345 ;
     RECT  2.16 6.615 28.08 6.885 ;
     RECT  2.16 7.155 28.08 7.425 ;
     RECT  2.16 7.695 28.08 7.965 ;
     RECT  2.16 8.235 28.08 8.505 ;
     RECT  2.16 8.775 28.08 9.045 ;
     RECT  2.16 9.315 28.08 9.585 ;
     RECT  2.16 9.855 28.08 10.125 ;
     RECT  2.16 10.395 28.08 10.665 ;
     RECT  2.16 10.935 28.08 11.205 ;
     RECT  2.16 11.475 28.08 11.745 ;
     RECT  2.16 12.015 28.08 12.285 ;
     RECT  2.16 12.555 28.08 12.825 ;
     RECT  2.16 13.095 28.08 13.365 ;
     RECT  2.16 13.635 28.08 13.905 ;
     RECT  2.16 14.175 28.08 14.445 ;
     RECT  2.16 14.715 28.08 14.985 ;
     RECT  2.16 15.255 28.08 15.525 ;
     RECT  2.16 15.795 28.08 16.065 ;
     RECT  2.16 16.335 28.08 16.605 ;
     RECT  2.16 16.875 28.08 17.145 ;
     RECT  2.16 17.415 28.08 17.685 ;
     RECT  2.16 17.955 28.08 18.225 ;
     RECT  2.16 18.495 28.08 18.765 ;
     RECT  2.16 19.035 28.08 19.305 ;
     RECT  2.16 19.575 28.08 19.845 ;
     RECT  2.16 20.115 28.08 20.385 ;
     RECT  2.16 20.655 28.08 20.925 ;
     RECT  2.16 21.195 28.08 21.465 ;
     RECT  2.16 21.735 28.08 22.005 ;
     RECT  2.16 22.275 28.08 22.545 ;
     RECT  2.16 22.815 28.08 23.085 ;
     RECT  2.16 23.355 28.08 23.625 ;
     RECT  2.16 23.895 28.08 24.165 ;
     RECT  2.16 24.435 28.08 24.705 ;
     RECT  2.16 24.975 28.08 25.245 ;
     RECT  2.16 25.515 28.08 25.785 ;
     RECT  2.16 26.055 28.08 26.325 ;
     RECT  2.16 26.595 28.08 26.865 ;
     RECT  2.16 27.135 28.08 27.405 ;
     RECT  2.16 27.675 28.08 27.945 ;
    LAYER M1 ;
     RECT  2.16 2.151 28.08 28.089 ;
    LAYER M2 ;
     RECT  0.103 10.71 2.16 10.728 ;
     RECT  0.535 11.826 2.16 11.844 ;
     RECT  0.103 17.082 2.16 17.1 ;
     RECT  2.16 2.151 11.371 28.089 ;
     RECT  11.371 2.106 12.443 28.089 ;
     RECT  12.443 2.151 17.959 28.089 ;
     RECT  17.959 1.881 18.031 28.089 ;
     RECT  18.031 1.422 18.319 28.089 ;
     RECT  18.319 0.846 25.223 28.089 ;
     RECT  25.223 0.846 25.295 0.864 ;
     RECT  25.303 0.531 26.015 0.549 ;
     RECT  25.223 1.728 26.195 28.089 ;
     RECT  26.195 1.962 27.599 28.089 ;
     RECT  27.599 2.151 28.08 28.089 ;
     RECT  28.08 2.268 28.103 2.286 ;
     RECT  28.08 4.5 28.103 5.904 ;
     RECT  28.08 6.66 28.103 17.478 ;
     RECT  28.103 7.938 28.139 17.478 ;
     RECT  28.139 7.938 28.175 11.736 ;
     RECT  28.139 12.726 28.211 17.478 ;
     RECT  28.103 4.734 28.319 5.904 ;
     RECT  28.175 8.748 28.715 11.736 ;
     RECT  28.715 8.748 28.751 10.656 ;
     RECT  28.211 12.726 28.751 16.974 ;
     RECT  28.319 5.202 28.895 5.904 ;
     RECT  28.895 5.202 29.003 5.364 ;
     RECT  29.003 5.202 29.039 5.22 ;
     RECT  28.751 9.756 29.039 10.656 ;
     RECT  29.039 9.864 29.075 10.656 ;
     RECT  28.751 12.726 29.507 16.938 ;
     RECT  29.507 12.726 29.543 16.596 ;
     RECT  29.075 10.026 29.651 10.656 ;
     RECT  29.543 13.536 29.651 16.596 ;
     RECT  28.751 8.748 29.687 8.964 ;
     RECT  28.715 11.718 29.767 11.736 ;
     RECT  29.543 12.726 29.803 12.744 ;
     RECT  29.803 12.564 29.831 12.744 ;
     RECT  29.651 13.536 29.867 16.434 ;
     RECT  28.103 6.66 29.911 7.182 ;
     RECT  28.175 7.938 29.911 7.956 ;
     RECT  29.831 12.564 29.939 12.582 ;
     RECT  29.911 6.66 30.011 7.956 ;
     RECT  29.867 13.68 30.047 16.434 ;
     RECT  29.767 11.484 30.055 11.736 ;
     RECT  29.687 8.901 30.083 8.964 ;
     RECT  29.651 10.026 30.083 10.044 ;
     RECT  30.047 13.68 30.083 15.894 ;
     RECT  30.083 14.346 30.119 14.859 ;
     RECT  30.011 6.66 30.155 7.182 ;
     RECT  30.011 7.938 30.155 7.956 ;
     RECT  30.055 11.412 30.155 11.736 ;
     RECT  30.119 14.652 30.155 14.859 ;
     RECT  30.155 11.412 30.191 11.43 ;
     RECT  30.155 14.652 30.191 14.67 ;
     RECT  30.083 8.901 30.227 8.919 ;
     RECT  30.083 15.876 30.227 15.894 ;
    LAYER M3 ;
     RECT  28.548 0.043 28.566 0.091 ;
     RECT  23.472 0.091 23.49 0.139 ;
     RECT  24.228 0.091 24.246 0.139 ;
     RECT  24.984 0.091 25.218 0.139 ;
     RECT  19.584 0.043 19.602 0.187 ;
     RECT  19.584 0.187 19.998 0.235 ;
     RECT  19.584 0.235 20.43 0.283 ;
     RECT  23.472 0.139 24.246 0.331 ;
     RECT  24.984 0.139 25.29 0.52 ;
     RECT  26.352 0.091 26.37 0.52 ;
     RECT  24.984 0.52 26.37 0.571 ;
     RECT  27.468 0.091 29.07 0.571 ;
     RECT  21.708 0.523 21.726 0.715 ;
     RECT  19.584 0.283 20.826 0.763 ;
     RECT  18.576 0.811 18.594 0.841 ;
     RECT  18.324 0.841 18.594 0.859 ;
     RECT  23.004 0.331 24.246 0.905 ;
     RECT  19.512 0.763 20.826 0.913 ;
     RECT  21.708 0.715 22.014 0.913 ;
     RECT  24.228 0.905 24.246 0.941 ;
     RECT  18.144 0.859 18.594 0.955 ;
     RECT  19.512 0.913 22.014 0.955 ;
     RECT  18.144 0.955 22.014 1.417 ;
     RECT  23.004 0.905 23.49 1.531 ;
     RECT  22.824 1.531 23.49 1.759 ;
     RECT  18.036 1.417 22.014 1.795 ;
     RECT  22.824 1.759 24.066 1.795 ;
     RECT  18.036 1.795 24.066 1.876 ;
     RECT  17.964 1.876 24.066 2.065 ;
     RECT  24.984 0.571 29.07 2.065 ;
     RECT  5.115 2.143 5.205 2.191 ;
     RECT  7.815 2.143 7.905 2.191 ;
     RECT  10.515 2.143 10.605 2.191 ;
     RECT  11.376 2.101 11.394 2.191 ;
     RECT  12.42 2.101 12.438 2.191 ;
     RECT  13.215 2.143 13.305 2.191 ;
     RECT  15.915 2.143 16.005 2.191 ;
     RECT  4.68 2.191 5.205 2.263 ;
     RECT  7.2 2.191 7.905 2.293 ;
     RECT  9.9 2.191 11.394 2.299 ;
     RECT  12.42 2.191 13.305 2.299 ;
     RECT  15.12 2.293 15.138 2.299 ;
     RECT  4.608 2.263 5.205 2.335 ;
     RECT  7.2 2.293 8.37 2.335 ;
     RECT  9.9 2.299 13.305 2.335 ;
     RECT  14.76 2.299 15.138 2.335 ;
     RECT  15.876 2.191 16.005 2.335 ;
     RECT  9.864 2.335 13.734 2.347 ;
     RECT  14.76 2.335 16.005 2.347 ;
     RECT  4.392 2.335 5.205 2.371 ;
     RECT  2.415 2.143 2.505 2.413 ;
     RECT  9.864 2.347 16.005 2.413 ;
     RECT  7.164 2.335 8.37 2.443 ;
     RECT  9.108 2.299 9.126 2.443 ;
     RECT  4.392 2.371 5.814 2.461 ;
     RECT  4.392 2.461 5.886 2.497 ;
     RECT  7.164 2.443 9.126 2.497 ;
     RECT  9.864 2.413 16.197 2.497 ;
     RECT  7.164 2.497 16.506 2.533 ;
     RECT  4.356 2.497 5.886 2.569 ;
     RECT  6.804 2.533 16.506 2.569 ;
     RECT  3.636 2.569 16.506 2.641 ;
     RECT  2.415 2.413 2.697 2.875 ;
     RECT  3.636 2.641 16.974 2.875 ;
     RECT  17.964 2.065 29.07 2.875 ;
     RECT  2.415 2.875 2.754 3.037 ;
     RECT  3.636 2.875 29.07 3.037 ;
     RECT  2.415 3.037 29.07 4.019 ;
     RECT  3.708 4.019 29.07 4.253 ;
     RECT  3.744 4.253 29.07 4.685 ;
     RECT  2.415 4.019 2.898 4.999 ;
     RECT  3.744 4.685 9.342 4.999 ;
     RECT  2.415 4.999 9.342 5.029 ;
     RECT  2.34 5.029 9.342 5.069 ;
     RECT  10.08 4.685 29.07 5.789 ;
     RECT  2.415 5.069 9.342 6.115 ;
     RECT  2.415 6.115 9.45 6.619 ;
     RECT  10.224 5.789 29.07 6.619 ;
     RECT  2.415 6.619 29.07 6.763 ;
     RECT  2.376 6.763 29.07 6.781 ;
     RECT  30.132 6.655 30.15 6.853 ;
     RECT  2.376 6.781 29.106 6.893 ;
     RECT  2.376 6.893 29.07 6.989 ;
     RECT  2.376 6.989 5.634 7.231 ;
     RECT  29.952 6.853 30.15 7.387 ;
     RECT  2.34 7.231 5.634 7.735 ;
     RECT  6.48 6.989 29.07 7.735 ;
     RECT  2.34 7.735 29.07 7.819 ;
     RECT  29.916 7.387 30.15 7.819 ;
     RECT  2.34 7.819 30.15 8.465 ;
     RECT  10.368 8.465 30.15 8.501 ;
     RECT  10.476 8.501 30.15 8.896 ;
     RECT  10.476 8.896 30.222 9.259 ;
     RECT  2.34 8.465 9.63 9.553 ;
     RECT  10.44 9.259 30.222 9.553 ;
     RECT  2.34 9.553 30.222 10.975 ;
     RECT  0.108 10.705 0.126 11.117 ;
     RECT  2.232 10.975 30.222 11.405 ;
     RECT  0.54 11.821 0.558 12.077 ;
     RECT  2.304 11.405 30.222 12.907 ;
     RECT  2.268 12.907 30.222 13.003 ;
     RECT  2.232 13.003 30.222 13.325 ;
     RECT  2.304 13.325 30.222 13.595 ;
     RECT  2.376 13.595 30.222 13.865 ;
     RECT  2.415 13.865 30.222 15.835 ;
     RECT  2.376 15.835 30.222 15.899 ;
     RECT  2.376 15.899 30.042 16.439 ;
     RECT  2.376 16.439 29.646 16.555 ;
     RECT  2.34 16.555 29.646 16.601 ;
     RECT  2.34 16.601 29.502 16.709 ;
     RECT  29.484 16.709 29.502 16.943 ;
     RECT  2.34 16.709 28.746 16.979 ;
     RECT  2.34 16.979 28.206 17.105 ;
     RECT  0.108 17.077 0.126 17.165 ;
     RECT  27.792 17.105 28.206 17.339 ;
     RECT  28.188 17.339 28.206 17.483 ;
     RECT  2.34 17.105 26.997 18.221 ;
     RECT  2.415 18.221 26.997 18.265 ;
     RECT  2.415 18.265 27.09 18.301 ;
     RECT  2.415 18.301 27.306 18.535 ;
     RECT  2.415 18.535 27.954 18.689 ;
     RECT  2.415 18.689 27.522 18.725 ;
     RECT  2.415 18.725 27.09 19.229 ;
     RECT  2.415 19.229 26.997 19.531 ;
     RECT  2.376 19.531 26.997 20.731 ;
     RECT  2.376 20.731 27.054 20.849 ;
     RECT  2.415 20.849 27.054 21.811 ;
     RECT  2.415 21.811 27.522 21.973 ;
     RECT  2.415 21.973 27.63 22.009 ;
     RECT  2.34 22.009 27.63 22.061 ;
     RECT  2.415 22.061 27.63 22.081 ;
     RECT  2.415 22.081 27.954 22.199 ;
     RECT  2.415 22.199 27.63 24.241 ;
     RECT  2.415 24.241 27.918 24.503 ;
     RECT  2.415 24.503 27.63 26.107 ;
     RECT  2.376 26.107 27.63 26.159 ;
     RECT  2.415 26.159 27.63 26.671 ;
     RECT  2.415 26.671 27.666 26.789 ;
     RECT  2.415 26.789 27.414 26.897 ;
     RECT  12.06 26.897 27.414 27.095 ;
     RECT  12.06 27.095 26.997 27.203 ;
     RECT  2.415 26.897 11.178 27.329 ;
     RECT  2.415 27.329 10.962 27.389 ;
     RECT  2.415 27.389 10.926 27.401 ;
     RECT  2.415 27.401 9.414 27.509 ;
     RECT  2.415 27.509 6.174 27.599 ;
     RECT  7.416 27.509 9.414 27.599 ;
     RECT  10.368 27.401 10.926 27.599 ;
     RECT  12.06 27.203 25.866 27.599 ;
     RECT  7.668 27.599 9.414 27.635 ;
     RECT  25.416 27.599 25.866 27.635 ;
     RECT  7.668 27.635 9.234 27.671 ;
     RECT  12.06 27.599 24.606 27.671 ;
     RECT  10.368 27.599 10.797 27.707 ;
     RECT  7.668 27.671 8.097 27.743 ;
     RECT  9.216 27.671 9.234 27.743 ;
     RECT  25.524 27.635 25.866 27.779 ;
     RECT  2.415 27.599 5.397 27.827 ;
     RECT  7.815 27.743 8.097 27.827 ;
     RECT  10.515 27.707 10.797 27.827 ;
     RECT  12.528 27.671 24.297 27.827 ;
     RECT  26.715 27.203 26.997 27.827 ;
     RECT  2.415 27.827 5.274 27.841 ;
     RECT  2.376 27.841 5.274 27.869 ;
     RECT  12.528 27.827 24.105 27.869 ;
     RECT  2.376 27.869 3.33 27.905 ;
     RECT  4.284 27.869 4.302 27.905 ;
     RECT  12.96 27.869 20.502 27.905 ;
     RECT  21.315 27.869 24.105 27.905 ;
     RECT  25.596 27.779 25.866 27.905 ;
     RECT  2.376 27.905 2.505 27.917 ;
     RECT  21.315 27.905 22.986 27.917 ;
     RECT  3.312 27.905 3.33 27.941 ;
     RECT  13.215 27.905 17.442 27.941 ;
     RECT  18.288 27.905 20.502 27.941 ;
     RECT  21.315 27.917 22.086 27.941 ;
     RECT  22.968 27.917 22.986 27.941 ;
     RECT  23.976 27.905 24.105 27.941 ;
     RECT  25.848 27.905 25.866 27.941 ;
     RECT  13.215 27.941 17.046 28.013 ;
     RECT  13.215 28.013 16.938 28.061 ;
     RECT  2.415 27.917 2.505 28.097 ;
     RECT  5.115 27.869 5.205 28.097 ;
     RECT  7.815 27.827 7.905 28.097 ;
     RECT  10.515 27.827 10.605 28.097 ;
     RECT  13.215 28.061 15.138 28.097 ;
     RECT  18.615 27.941 20.502 28.097 ;
     RECT  21.315 27.941 21.405 28.097 ;
     RECT  24.015 27.941 24.105 28.097 ;
     RECT  26.715 27.827 26.805 28.097 ;
     RECT  13.752 28.097 15.138 28.157 ;
     RECT  15.876 28.061 16.938 28.253 ;
     RECT  19.152 28.097 20.502 28.493 ;
     RECT  13.752 28.157 14.922 28.541 ;
     RECT  13.752 28.541 14.454 28.637 ;
     RECT  13.752 28.637 14.202 29.597 ;
     RECT  14.184 29.597 14.202 29.645 ;
     RECT  19.152 28.493 19.17 29.645 ;
     RECT  16.416 28.253 16.938 29.693 ;
     RECT  16.344 29.899 16.362 30.125 ;
    LAYER M4 ;
     RECT  0.084 11.088 0.137 11.112 ;
     RECT  0.06 11.112 0.137 11.184 ;
     RECT  0.084 11.184 0.137 11.208 ;
     RECT  0.06 11.208 0.137 11.28 ;
     RECT  0.084 11.28 0.137 11.304 ;
     RECT  0.06 11.304 0.137 11.376 ;
     RECT  0.084 11.376 0.137 11.4 ;
     RECT  0.06 11.4 0.137 11.472 ;
     RECT  0.084 11.472 0.137 11.496 ;
     RECT  0.06 11.496 0.137 11.568 ;
     RECT  0.084 11.568 0.137 11.592 ;
     RECT  0.06 11.592 0.137 11.664 ;
     RECT  0.084 11.664 0.137 11.688 ;
     RECT  0.06 11.688 0.137 11.76 ;
     RECT  0.084 11.76 0.137 11.784 ;
     RECT  0.06 11.784 0.137 11.856 ;
     RECT  0.084 11.856 0.137 11.88 ;
     RECT  0.06 11.88 0.137 11.952 ;
     RECT  0.084 11.952 0.137 11.976 ;
     RECT  0.06 11.976 0.137 12.048 ;
     RECT  0.084 12.048 0.137 12.072 ;
     RECT  0.06 12.072 0.137 12.144 ;
     RECT  0.084 12.144 0.137 12.168 ;
     RECT  0.06 12.168 0.137 12.24 ;
     RECT  0.084 12.24 0.137 12.264 ;
     RECT  0.06 12.264 0.137 12.336 ;
     RECT  0.084 12.336 0.137 12.36 ;
     RECT  0.06 12.36 0.137 12.432 ;
     RECT  0.084 12.432 0.137 12.456 ;
     RECT  0.06 12.456 0.137 12.528 ;
     RECT  0.084 12.528 0.137 12.552 ;
     RECT  0.06 12.552 0.137 12.624 ;
     RECT  0.084 12.624 0.137 12.648 ;
     RECT  0.06 12.648 0.137 12.72 ;
     RECT  0.084 12.72 0.137 12.744 ;
     RECT  0.06 12.744 0.137 12.816 ;
     RECT  0.084 12.816 0.137 12.84 ;
     RECT  0.06 12.84 0.137 12.912 ;
     RECT  0.084 12.912 0.137 12.936 ;
     RECT  0.06 12.936 0.137 13.008 ;
     RECT  0.084 13.008 0.137 13.032 ;
     RECT  2.285 18.192 2.293 18.216 ;
     RECT  2.293 6.768 2.365 6.792 ;
     RECT  2.329 16.56 2.365 16.584 ;
     RECT  2.293 5.04 2.408 5.064 ;
     RECT  2.365 6.768 2.408 6.888 ;
     RECT  2.365 9.6 2.408 9.624 ;
     RECT  0.137 11.184 2.408 13.032 ;
     RECT  2.365 15.84 2.408 16.584 ;
     RECT  2.293 18.192 2.408 19.56 ;
     RECT  2.293 22.032 2.408 22.056 ;
     RECT  2.293 23.856 2.408 23.88 ;
     RECT  2.365 26.112 2.408 26.136 ;
     RECT  2.365 27.888 2.408 27.912 ;
     RECT  2.408 2.148 2.512 28.092 ;
     RECT  2.512 2.418 2.704 27.912 ;
     RECT  2.704 10.848 2.801 14.232 ;
     RECT  2.801 13.008 2.819 14.232 ;
     RECT  2.704 23.952 2.915 27.912 ;
     RECT  2.801 10.848 2.981 11.928 ;
     RECT  2.915 23.952 3.413 27.384 ;
     RECT  3.413 23.952 3.449 24.6 ;
     RECT  2.704 9.6 3.697 9.624 ;
     RECT  2.704 15.84 3.697 16.584 ;
     RECT  3.697 15.84 3.733 17.4 ;
     RECT  2.704 18.768 3.733 18.792 ;
     RECT  2.704 7.872 3.737 7.896 ;
     RECT  3.413 25.68 3.737 27.384 ;
     RECT  3.733 15.84 3.769 18.792 ;
     RECT  2.819 13.008 3.877 13.464 ;
     RECT  3.877 13.008 3.913 13.56 ;
     RECT  3.697 9.6 3.949 9.672 ;
     RECT  2.981 10.848 3.949 11.256 ;
     RECT  3.449 24.24 3.953 24.6 ;
     RECT  3.737 25.68 3.997 25.704 ;
     RECT  3.949 9.6 4.021 11.256 ;
     RECT  3.769 14.832 4.309 18.792 ;
     RECT  3.913 12.96 4.417 13.56 ;
     RECT  4.165 23.04 4.453 23.064 ;
     RECT  2.704 2.88 4.489 2.904 ;
     RECT  4.417 12.336 4.489 13.56 ;
     RECT  4.309 14.832 4.489 19.032 ;
     RECT  2.704 6.624 4.549 6.888 ;
     RECT  4.021 9.6 4.549 11.352 ;
     RECT  4.489 12.336 4.561 13.608 ;
     RECT  3.769 20.688 4.633 20.712 ;
     RECT  4.453 23.04 4.633 23.304 ;
     RECT  4.633 20.688 4.705 21.096 ;
     RECT  4.549 9.456 4.957 11.352 ;
     RECT  4.561 12.336 4.957 13.704 ;
     RECT  4.489 14.832 4.957 19.32 ;
     RECT  4.957 9.456 5.065 13.704 ;
     RECT  4.957 14.832 5.065 19.56 ;
     RECT  3.737 27.36 5.101 27.384 ;
     RECT  4.489 2.88 5.108 3.432 ;
     RECT  4.549 5.856 5.108 6.888 ;
     RECT  4.309 7.968 5.108 7.992 ;
     RECT  5.065 9.456 5.108 19.56 ;
     RECT  4.705 20.688 5.108 21.672 ;
     RECT  4.633 22.752 5.108 23.304 ;
     RECT  3.953 24.576 5.108 24.6 ;
     RECT  5.101 27.12 5.108 27.384 ;
     RECT  5.108 2.148 5.212 28.092 ;
     RECT  5.212 2.418 5.404 27.822 ;
     RECT  5.404 23.04 5.465 23.304 ;
     RECT  5.404 11.232 5.573 11.544 ;
     RECT  5.404 18 5.609 21.816 ;
     RECT  5.609 20.544 5.789 21.816 ;
     RECT  5.404 12.864 6.221 14.184 ;
     RECT  5.404 7.968 6.329 9.336 ;
     RECT  5.404 25.2 6.365 25.368 ;
     RECT  5.404 26.88 6.365 27.384 ;
     RECT  6.365 26.88 6.397 27.336 ;
     RECT  6.329 7.968 6.401 8.28 ;
     RECT  5.609 18 6.473 19.32 ;
     RECT  5.789 20.688 6.473 21.816 ;
     RECT  6.473 21.744 6.505 21.816 ;
     RECT  6.473 20.688 6.509 20.712 ;
     RECT  6.397 26.784 6.545 27.336 ;
     RECT  6.221 12.864 6.725 13.944 ;
     RECT  6.329 9.312 6.761 9.336 ;
     RECT  6.401 8.112 6.833 8.28 ;
     RECT  5.404 3.408 7.009 4.776 ;
     RECT  7.009 3.408 7.141 5.112 ;
     RECT  6.473 18 7.153 18.984 ;
     RECT  7.153 17.136 7.189 18.984 ;
     RECT  7.141 2.544 7.513 5.112 ;
     RECT  7.513 2.544 7.585 5.88 ;
     RECT  7.189 16.512 7.669 18.984 ;
     RECT  7.585 2.304 7.808 5.88 ;
     RECT  6.833 8.112 7.808 8.232 ;
     RECT  7.297 9.936 7.808 9.96 ;
     RECT  5.573 11.232 7.808 11.256 ;
     RECT  6.725 12.864 7.808 13.896 ;
     RECT  7.669 16.512 7.808 19.8 ;
     RECT  6.505 21.744 7.808 22.008 ;
     RECT  5.465 23.04 7.808 23.064 ;
     RECT  6.365 25.344 7.808 25.368 ;
     RECT  6.545 27.12 7.808 27.336 ;
     RECT  7.808 2.148 7.912 28.092 ;
     RECT  7.912 2.304 8.104 27.822 ;
     RECT  8.104 21.792 8.237 22.008 ;
     RECT  8.104 12.336 8.309 13.896 ;
     RECT  8.104 2.304 8.381 2.472 ;
     RECT  8.237 21.984 8.597 22.008 ;
     RECT  8.104 4.224 8.813 6.072 ;
     RECT  8.309 12.336 8.849 13.032 ;
     RECT  8.104 16.416 8.993 17.208 ;
     RECT  8.813 4.224 9.029 4.968 ;
     RECT  8.813 6.048 9.029 6.072 ;
     RECT  8.104 11.232 9.029 11.256 ;
     RECT  8.993 16.896 9.133 17.208 ;
     RECT  8.104 18.432 9.133 19.368 ;
     RECT  8.104 25.584 9.133 25.608 ;
     RECT  8.104 23.04 9.169 23.112 ;
     RECT  9.133 25.584 9.169 25.992 ;
     RECT  9.133 16.896 9.209 19.368 ;
     RECT  8.104 7.872 9.277 7.896 ;
     RECT  8.849 12.336 9.317 12.888 ;
     RECT  9.209 17.088 9.425 19.368 ;
     RECT  9.425 17.088 9.461 19.272 ;
     RECT  9.169 25.44 9.461 25.992 ;
     RECT  9.461 25.536 9.533 25.992 ;
     RECT  9.277 7.872 9.961 7.992 ;
     RECT  9.961 7.728 10.028 7.992 ;
     RECT  9.169 22.032 10.141 23.112 ;
     RECT  9.997 24.144 10.141 24.168 ;
     RECT  10.141 27.36 10.249 27.384 ;
     RECT  10.141 22.032 10.285 24.168 ;
     RECT  9.385 15.168 10.321 15.192 ;
     RECT  10.357 9.264 10.429 9.288 ;
     RECT  8.381 2.448 10.508 2.472 ;
     RECT  9.029 4.224 10.508 4.536 ;
     RECT  10.028 5.76 10.508 5.784 ;
     RECT  10.028 7.344 10.508 7.992 ;
     RECT  10.429 9.264 10.508 9.816 ;
     RECT  9.317 12.864 10.508 12.888 ;
     RECT  10.321 15.168 10.508 16.008 ;
     RECT  9.461 17.616 10.508 19.272 ;
     RECT  10.501 20.352 10.508 20.376 ;
     RECT  10.285 21.504 10.508 24.168 ;
     RECT  9.533 25.536 10.508 25.56 ;
     RECT  10.249 26.88 10.508 27.384 ;
     RECT  10.508 2.148 10.612 28.092 ;
     RECT  10.612 2.418 10.804 27.822 ;
     RECT  10.804 4.224 10.829 4.392 ;
     RECT  10.804 25.056 10.972 27.384 ;
     RECT  10.972 25.488 10.973 27.384 ;
     RECT  10.804 17.088 10.979 23.304 ;
     RECT  10.973 25.488 11.009 26.904 ;
     RECT  10.979 17.616 11.027 23.304 ;
     RECT  11.009 25.536 11.081 26.904 ;
     RECT  11.081 25.536 11.117 26.088 ;
     RECT  10.804 2.448 11.189 2.856 ;
     RECT  11.027 17.616 11.189 17.64 ;
     RECT  10.804 14.832 11.225 16.056 ;
     RECT  10.804 8.832 11.267 11.016 ;
     RECT  11.267 10.032 11.405 11.016 ;
     RECT  11.117 25.728 11.405 26.088 ;
     RECT  11.405 25.728 11.513 25.752 ;
     RECT  11.189 2.544 11.765 2.856 ;
     RECT  10.804 6.048 11.797 6.12 ;
     RECT  10.804 7.68 11.797 7.752 ;
     RECT  11.225 16.032 11.909 16.056 ;
     RECT  10.829 4.368 11.941 4.392 ;
     RECT  11.027 19.344 11.941 23.304 ;
     RECT  11.941 3.936 12.049 4.392 ;
     RECT  12.049 3.936 12.337 4.488 ;
     RECT  11.941 19.344 12.373 23.4 ;
     RECT  12.049 27.36 12.469 27.384 ;
     RECT  11.225 14.832 12.553 14.856 ;
     RECT  11.405 10.032 12.625 10.056 ;
     RECT  12.373 19.344 12.841 23.64 ;
     RECT  11.765 2.832 12.877 2.856 ;
     RECT  11.797 6.048 12.956 7.752 ;
     RECT  12.841 18.624 12.985 23.64 ;
     RECT  11.267 8.832 13.093 8.856 ;
     RECT  12.625 9.84 13.093 10.056 ;
     RECT  12.337 11.952 13.093 11.976 ;
     RECT  10.804 13.008 13.093 13.08 ;
     RECT  12.877 2.352 13.208 2.856 ;
     RECT  12.337 3.936 13.208 4.536 ;
     RECT  12.956 5.52 13.208 7.752 ;
     RECT  13.093 8.832 13.208 10.056 ;
     RECT  13.093 11.952 13.208 13.08 ;
     RECT  12.553 14.784 13.208 14.856 ;
     RECT  13.045 16.368 13.208 16.392 ;
     RECT  12.661 17.616 13.208 17.64 ;
     RECT  12.985 18.624 13.208 24.12 ;
     RECT  13.129 25.2 13.208 25.224 ;
     RECT  12.469 26.64 13.208 27.384 ;
     RECT  13.208 2.148 13.312 28.092 ;
     RECT  13.312 2.352 13.504 28.092 ;
     RECT  13.504 22.368 13.709 24.12 ;
     RECT  13.504 3.936 13.781 4.392 ;
     RECT  13.504 26.256 13.853 28.092 ;
     RECT  13.709 22.368 13.859 24.072 ;
     RECT  13.504 25.2 13.859 25.224 ;
     RECT  13.741 29.568 14.101 29.592 ;
     RECT  13.504 6.672 14.105 10.44 ;
     RECT  13.853 27.936 14.137 28.092 ;
     RECT  14.101 29.088 14.137 29.592 ;
     RECT  14.137 27.936 14.173 29.592 ;
     RECT  14.173 27.936 14.291 29.64 ;
     RECT  14.291 27.936 14.387 29.592 ;
     RECT  13.504 20.304 14.533 20.328 ;
     RECT  14.387 27.936 14.579 29.112 ;
     RECT  14.533 19.968 14.641 20.328 ;
     RECT  14.641 19.968 14.713 21 ;
     RECT  13.504 14.976 14.732 15 ;
     RECT  14.605 25.056 14.741 25.08 ;
     RECT  13.504 2.352 14.749 2.376 ;
     RECT  14.732 14.976 14.749 15.096 ;
     RECT  13.504 16.368 14.749 16.392 ;
     RECT  14.605 18.816 14.785 18.84 ;
     RECT  14.713 19.968 14.785 21.192 ;
     RECT  14.105 7.44 14.819 10.44 ;
     RECT  14.749 2.304 14.821 2.376 ;
     RECT  14.819 7.632 14.825 10.44 ;
     RECT  14.785 18.816 14.857 21.192 ;
     RECT  13.504 11.952 14.924 13.848 ;
     RECT  14.749 14.976 14.924 16.392 ;
     RECT  13.781 4.128 14.929 4.392 ;
     RECT  14.825 7.68 15.001 10.44 ;
     RECT  14.579 27.936 15.059 28.632 ;
     RECT  14.857 18.432 15.073 21.192 ;
     RECT  14.741 25.008 15.116 25.08 ;
     RECT  13.853 26.256 15.116 26.808 ;
     RECT  14.785 17.424 15.181 17.448 ;
     RECT  15.073 18.432 15.181 21.24 ;
     RECT  13.859 22.368 15.308 23.976 ;
     RECT  15.116 25.008 15.308 26.808 ;
     RECT  14.497 6.384 15.361 6.408 ;
     RECT  15.001 7.68 15.577 10.824 ;
     RECT  14.924 11.952 15.577 16.392 ;
     RECT  14.929 3.936 15.613 4.392 ;
     RECT  15.613 3.936 15.685 4.68 ;
     RECT  15.181 17.424 15.765 21.24 ;
     RECT  15.308 22.368 15.765 26.808 ;
     RECT  14.821 2.304 15.908 2.424 ;
     RECT  15.685 3.696 15.908 4.68 ;
     RECT  15.361 6.048 15.908 6.408 ;
     RECT  15.577 7.68 15.908 16.392 ;
     RECT  15.765 17.424 15.908 26.808 ;
     RECT  15.059 27.936 15.908 28.536 ;
     RECT  15.908 2.148 16.012 28.536 ;
     RECT  16.012 2.304 16.013 28.536 ;
     RECT  15.973 29.616 16.165 29.64 ;
     RECT  16.013 2.418 16.204 28.536 ;
     RECT  16.165 29.616 16.261 29.976 ;
     RECT  16.204 21.696 16.265 28.536 ;
     RECT  16.261 29.616 16.333 30.024 ;
     RECT  16.204 15.216 16.381 19.176 ;
     RECT  16.381 15.216 16.396 19.032 ;
     RECT  16.396 15.216 16.417 17.16 ;
     RECT  16.333 29.616 16.417 30.12 ;
     RECT  16.417 29.616 16.547 30.024 ;
     RECT  16.547 29.616 16.549 29.688 ;
     RECT  16.549 29.04 16.633 29.688 ;
     RECT  16.204 3.408 16.697 5.16 ;
     RECT  16.265 21.696 16.805 28.056 ;
     RECT  16.805 21.696 16.883 25.032 ;
     RECT  16.633 29.664 16.949 29.688 ;
     RECT  16.204 8.832 17.021 10.632 ;
     RECT  16.805 26.112 17.075 28.056 ;
     RECT  17.075 26.112 17.093 27.864 ;
     RECT  16.396 18.24 17.165 19.032 ;
     RECT  16.883 21.936 17.165 25.032 ;
     RECT  16.204 12.288 17.197 12.792 ;
     RECT  17.197 12.288 17.269 13.32 ;
     RECT  16.417 15.216 17.273 17.064 ;
     RECT  16.204 6.288 17.305 6.408 ;
     RECT  16.204 7.392 17.305 7.416 ;
     RECT  17.021 9.024 17.305 10.632 ;
     RECT  17.273 17.04 17.309 17.064 ;
     RECT  17.305 6.288 17.345 7.992 ;
     RECT  17.273 15.216 17.365 15.24 ;
     RECT  16.697 4.464 17.485 5.16 ;
     RECT  17.345 6.288 17.485 6.888 ;
     RECT  16.697 3.408 17.521 3.432 ;
     RECT  17.165 18.432 17.593 19.032 ;
     RECT  17.521 3.072 17.629 3.432 ;
     RECT  17.269 12.192 17.633 13.32 ;
     RECT  17.365 14.832 17.665 15.24 ;
     RECT  17.593 18.432 17.701 19.272 ;
     RECT  17.701 18.432 17.737 19.32 ;
     RECT  17.737 18.432 17.881 20.088 ;
     RECT  17.629 2.88 18.097 3.432 ;
     RECT  17.485 4.464 18.097 6.888 ;
     RECT  17.305 9.024 18.241 10.776 ;
     RECT  17.633 12.192 18.241 12.888 ;
     RECT  17.345 7.968 18.285 7.992 ;
     RECT  18.241 9.024 18.285 12.888 ;
     RECT  18.097 2.592 18.349 6.888 ;
     RECT  18.285 7.968 18.349 12.888 ;
     RECT  17.881 18.432 18.349 20.472 ;
     RECT  18.349 2.592 18.493 12.888 ;
     RECT  18.133 0.864 18.565 0.888 ;
     RECT  17.165 21.984 18.565 25.032 ;
     RECT  18.493 2.544 18.608 12.888 ;
     RECT  17.665 14.4 18.608 15.24 ;
     RECT  18.349 18.24 18.608 20.472 ;
     RECT  18.565 21.792 18.608 25.032 ;
     RECT  17.093 26.112 18.608 27.336 ;
     RECT  18.608 2.148 18.712 28.092 ;
     RECT  18.712 2.148 18.745 27.96 ;
     RECT  18.745 1.968 18.904 27.96 ;
     RECT  18.904 14.4 19.001 14.424 ;
     RECT  18.565 0.816 19.069 0.888 ;
     RECT  18.904 17.088 19.109 20.76 ;
     RECT  19.109 17.088 19.145 19.32 ;
     RECT  19.069 0.816 19.213 0.984 ;
     RECT  18.904 1.968 19.213 12.552 ;
     RECT  19.145 17.088 19.253 19.272 ;
     RECT  19.253 17.088 19.325 19.08 ;
     RECT  19.213 0.816 19.501 12.552 ;
     RECT  19.501 0.768 19.573 12.552 ;
     RECT  19.141 29.616 19.667 29.64 ;
     RECT  18.904 27.936 19.681 27.96 ;
     RECT  18.904 23.136 19.973 26.808 ;
     RECT  19.109 20.4 20.077 20.76 ;
     RECT  18.904 21.744 20.077 22.056 ;
     RECT  19.973 23.136 20.189 25.704 ;
     RECT  20.077 20.4 20.221 22.056 ;
     RECT  20.189 23.136 20.221 23.16 ;
     RECT  18.904 15.984 20.293 16.008 ;
     RECT  19.325 17.088 20.293 18.456 ;
     RECT  19.973 26.688 20.437 26.808 ;
     RECT  19.681 27.936 20.437 28.488 ;
     RECT  20.437 26.688 20.513 28.488 ;
     RECT  20.041 14.928 20.653 14.952 ;
     RECT  20.293 15.984 20.653 18.456 ;
     RECT  19.573 0.048 21.013 12.552 ;
     RECT  20.473 13.536 21.013 13.56 ;
     RECT  20.221 20.4 21.061 23.16 ;
     RECT  21.013 0.048 21.157 13.56 ;
     RECT  20.653 14.928 21.157 18.456 ;
     RECT  21.061 19.872 21.301 23.16 ;
     RECT  20.189 24.432 21.301 25.704 ;
     RECT  21.157 0.048 21.308 18.456 ;
     RECT  21.301 19.872 21.308 25.704 ;
     RECT  20.513 26.688 21.308 28.092 ;
     RECT  21.308 0.048 21.412 28.092 ;
     RECT  21.412 0.048 21.604 27.912 ;
     RECT  21.604 26.112 21.737 26.136 ;
     RECT  21.604 0.048 21.773 25.032 ;
     RECT  21.773 24.096 22.205 25.032 ;
     RECT  21.773 0.048 22.277 22.056 ;
     RECT  22.277 14.784 22.457 22.056 ;
     RECT  21.604 27.36 22.853 27.912 ;
     RECT  22.853 27.888 22.997 27.912 ;
     RECT  22.277 0.048 23.413 13.608 ;
     RECT  22.457 14.784 23.413 21.72 ;
     RECT  23.413 0.048 24.008 21.72 ;
     RECT  23.641 23.28 24.008 23.304 ;
     RECT  22.205 24.432 24.008 25.032 ;
     RECT  24.008 0.048 24.112 28.092 ;
     RECT  24.112 0.048 24.304 27.822 ;
     RECT  24.304 0.048 24.509 19.32 ;
     RECT  24.304 20.64 24.509 23.304 ;
     RECT  24.509 14.64 24.545 19.32 ;
     RECT  24.304 24.432 24.545 25.032 ;
     RECT  24.545 16.368 24.581 19.32 ;
     RECT  24.545 24.48 24.725 25.032 ;
     RECT  24.509 20.88 24.797 23.304 ;
     RECT  24.797 23.28 24.977 23.304 ;
     RECT  24.545 14.64 25.085 15 ;
     RECT  24.797 20.88 25.121 22.2 ;
     RECT  24.509 0.048 25.193 13.656 ;
     RECT  25.121 20.928 25.229 22.2 ;
     RECT  25.229 21.024 25.265 22.2 ;
     RECT  25.085 14.64 25.409 14.952 ;
     RECT  25.193 0.048 25.427 13.128 ;
     RECT  25.427 0.048 25.523 1.56 ;
     RECT  24.581 17.088 25.523 19.32 ;
     RECT  25.513 26.688 25.549 26.712 ;
     RECT  25.427 2.544 25.561 13.128 ;
     RECT  25.523 18 25.585 19.32 ;
     RECT  25.549 26.4 25.625 26.712 ;
     RECT  25.625 26.4 25.697 26.424 ;
     RECT  24.725 25.008 25.765 25.032 ;
     RECT  25.621 16.272 25.937 16.392 ;
     RECT  25.409 14.832 26.053 14.952 ;
     RECT  26.053 14.832 26.449 15 ;
     RECT  25.937 15.984 26.449 16.392 ;
     RECT  26.449 14.832 26.533 16.392 ;
     RECT  25.561 2.544 26.581 9.624 ;
     RECT  25.561 10.608 26.581 13.128 ;
     RECT  25.265 21.024 26.581 21.96 ;
     RECT  26.161 23.616 26.581 23.64 ;
     RECT  25.765 25.008 26.581 25.704 ;
     RECT  25.523 0.048 26.621 1.224 ;
     RECT  26.581 2.304 26.621 13.128 ;
     RECT  26.621 0.048 26.705 13.128 ;
     RECT  26.705 2.148 26.708 13.128 ;
     RECT  26.533 14.208 26.708 16.392 ;
     RECT  25.585 18 26.708 19.848 ;
     RECT  26.581 21.024 26.708 25.704 ;
     RECT  26.708 2.148 26.812 28.092 ;
     RECT  26.812 2.304 27.004 27.822 ;
     RECT  27.004 6.624 27.029 10.728 ;
     RECT  27.004 2.304 27.281 5.592 ;
     RECT  27.029 6.624 27.317 7.944 ;
     RECT  27.281 2.304 27.389 4.248 ;
     RECT  27.389 3.408 27.425 4.248 ;
     RECT  27.281 5.568 27.533 5.592 ;
     RECT  26.705 0.048 27.539 1.128 ;
     RECT  27.389 2.304 27.569 2.376 ;
     RECT  27.317 6.624 27.605 7.656 ;
     RECT  27.029 8.976 27.605 10.728 ;
     RECT  27.004 11.76 27.749 17.112 ;
     RECT  27.425 3.408 27.821 3.912 ;
     RECT  27.749 14.496 27.827 17.112 ;
     RECT  27.749 11.76 27.929 13.272 ;
     RECT  27.827 14.496 27.929 16.632 ;
     RECT  27.539 0.048 28.073 0.6 ;
     RECT  28.073 0.048 28.115 0.36 ;
     RECT  27.929 14.928 28.181 16.632 ;
     RECT  27.605 9.504 28.213 10.728 ;
     RECT  27.929 11.76 28.213 12.936 ;
     RECT  27.569 2.304 28.403 2.328 ;
     RECT  28.115 0.048 28.577 0.168 ;
     RECT  28.213 9.504 28.741 12.936 ;
     RECT  28.181 15.408 28.787 16.632 ;
     RECT  28.741 9.072 28.825 12.936 ;
     RECT  27.821 3.888 29.005 3.912 ;
     RECT  27.605 7.056 29.005 7.656 ;
     RECT  28.577 0.096 29.009 0.168 ;
     RECT  29.005 6.96 29.077 7.656 ;
     RECT  29.009 0.096 29.081 0.12 ;
     RECT  29.077 6.864 29.293 7.656 ;
     RECT  28.825 8.784 29.293 12.936 ;
     RECT  28.787 15.408 29.363 16.584 ;
     RECT  29.363 15.984 29.411 16.584 ;
     RECT  29.411 16.56 30.131 16.584 ;
     RECT  29.005 3.792 30.156 3.816 ;
     RECT  29.005 3.816 30.204 3.888 ;
     RECT  29.005 3.888 30.156 3.912 ;
     RECT  29.293 6.864 30.156 6.888 ;
     RECT  29.293 6.888 30.204 6.96 ;
     RECT  29.293 6.96 30.156 6.984 ;
     RECT  29.293 6.984 30.204 7.056 ;
     RECT  29.293 7.056 30.156 7.08 ;
     RECT  29.293 7.08 30.204 7.152 ;
     RECT  29.293 7.152 30.156 7.176 ;
     RECT  29.293 7.176 30.204 7.248 ;
     RECT  29.293 7.248 30.156 7.272 ;
     RECT  29.293 7.272 30.204 7.344 ;
     RECT  29.293 7.344 30.156 7.368 ;
     RECT  29.293 7.368 30.204 7.44 ;
     RECT  29.293 7.44 30.156 7.464 ;
     RECT  29.293 7.464 30.204 7.536 ;
     RECT  29.293 7.536 30.156 7.56 ;
     RECT  29.293 7.56 30.204 7.632 ;
     RECT  29.293 7.632 30.156 7.656 ;
     RECT  29.293 7.656 30.204 7.728 ;
     RECT  29.293 7.728 30.156 7.752 ;
     RECT  29.293 7.752 30.204 7.824 ;
     RECT  29.293 7.824 30.156 7.848 ;
     RECT  29.293 7.848 30.204 7.92 ;
     RECT  29.293 7.92 30.156 7.944 ;
     RECT  29.293 7.944 30.204 8.016 ;
     RECT  29.293 8.016 30.156 8.04 ;
     RECT  29.293 8.04 30.204 8.112 ;
     RECT  29.293 8.112 30.156 8.136 ;
     RECT  29.293 8.136 30.204 8.208 ;
     RECT  29.293 8.208 30.156 8.232 ;
     RECT  29.293 8.232 30.204 8.304 ;
     RECT  29.293 8.304 30.156 8.328 ;
     RECT  29.293 8.328 30.204 8.4 ;
     RECT  29.293 8.4 30.156 8.424 ;
     RECT  29.293 8.424 30.204 8.496 ;
     RECT  29.293 8.496 30.156 8.52 ;
     RECT  29.293 8.52 30.204 8.592 ;
     RECT  29.293 8.592 30.156 8.616 ;
     RECT  29.293 8.616 30.204 8.688 ;
     RECT  29.293 8.688 30.156 8.712 ;
     RECT  29.293 8.712 30.204 8.784 ;
     RECT  29.293 8.784 30.156 8.808 ;
     RECT  29.293 8.808 30.204 8.88 ;
     RECT  29.293 8.88 30.156 8.904 ;
     RECT  29.293 8.904 30.204 8.976 ;
     RECT  29.293 8.976 30.156 9 ;
     RECT  29.293 9 30.204 9.072 ;
     RECT  29.293 9.072 30.156 9.096 ;
     RECT  29.293 9.096 30.204 9.168 ;
     RECT  29.293 9.168 30.156 9.192 ;
     RECT  29.293 9.192 30.204 9.264 ;
     RECT  29.293 9.264 30.156 9.288 ;
     RECT  29.293 9.288 30.204 9.36 ;
     RECT  29.293 9.36 30.156 9.384 ;
     RECT  29.293 9.384 30.204 9.456 ;
     RECT  29.293 9.456 30.156 9.48 ;
     RECT  29.293 9.48 30.204 9.552 ;
     RECT  29.293 9.552 30.156 9.576 ;
     RECT  29.293 9.576 30.204 9.648 ;
     RECT  29.293 9.648 30.156 9.672 ;
     RECT  29.293 9.672 30.204 9.744 ;
     RECT  29.293 9.744 30.156 9.768 ;
     RECT  29.293 9.768 30.204 9.84 ;
     RECT  29.293 9.84 30.156 9.864 ;
     RECT  29.293 9.864 30.204 9.936 ;
     RECT  29.293 9.936 30.156 9.96 ;
     RECT  29.293 9.96 30.204 10.032 ;
     RECT  29.293 10.032 30.156 10.056 ;
     RECT  29.293 10.056 30.204 10.128 ;
     RECT  29.293 10.128 30.156 10.152 ;
     RECT  29.293 10.152 30.204 10.224 ;
     RECT  29.293 10.224 30.156 10.248 ;
     RECT  29.293 10.248 30.204 10.32 ;
     RECT  29.293 10.32 30.156 10.344 ;
     RECT  29.293 10.344 30.204 10.416 ;
     RECT  29.293 10.416 30.156 10.44 ;
     RECT  29.293 10.44 30.204 10.512 ;
     RECT  29.293 10.512 30.156 10.536 ;
     RECT  29.293 10.536 30.204 10.608 ;
     RECT  29.293 10.608 30.156 10.632 ;
     RECT  29.293 10.632 30.204 10.704 ;
     RECT  29.293 10.704 30.156 10.728 ;
     RECT  29.293 10.728 30.204 10.8 ;
     RECT  29.293 10.8 30.156 10.824 ;
     RECT  29.293 10.824 30.204 10.896 ;
     RECT  29.293 10.896 30.156 10.92 ;
     RECT  29.293 10.92 30.204 10.992 ;
     RECT  29.293 10.992 30.156 11.016 ;
     RECT  29.293 11.016 30.204 11.088 ;
     RECT  29.293 11.088 30.156 11.112 ;
     RECT  29.293 11.112 30.204 11.184 ;
     RECT  29.293 11.184 30.156 11.208 ;
     RECT  29.293 11.208 30.204 11.28 ;
     RECT  29.293 11.28 30.156 11.304 ;
     RECT  29.293 11.304 30.204 11.376 ;
     RECT  29.293 11.376 30.156 11.4 ;
     RECT  29.293 11.4 30.204 11.472 ;
     RECT  29.293 11.472 30.156 11.496 ;
     RECT  29.293 11.496 30.204 11.568 ;
     RECT  29.293 11.568 30.156 11.592 ;
     RECT  29.293 11.592 30.204 11.664 ;
     RECT  29.293 11.664 30.156 11.688 ;
     RECT  29.293 11.688 30.204 11.76 ;
     RECT  29.293 11.76 30.156 11.784 ;
     RECT  29.293 11.784 30.204 11.856 ;
     RECT  29.293 11.856 30.156 11.88 ;
     RECT  29.293 11.88 30.204 11.952 ;
     RECT  29.293 11.952 30.156 11.976 ;
     RECT  29.293 11.976 30.204 12.048 ;
     RECT  29.293 12.048 30.156 12.072 ;
     RECT  29.293 12.072 30.204 12.144 ;
     RECT  29.293 12.144 30.156 12.168 ;
     RECT  29.293 12.168 30.204 12.24 ;
     RECT  29.293 12.24 30.156 12.264 ;
     RECT  29.293 12.264 30.204 12.336 ;
     RECT  29.293 12.336 30.156 12.36 ;
     RECT  29.293 12.36 30.204 12.432 ;
     RECT  29.293 12.432 30.156 12.456 ;
     RECT  29.293 12.456 30.204 12.528 ;
     RECT  29.293 12.528 30.156 12.552 ;
     RECT  29.293 12.552 30.204 12.624 ;
     RECT  29.293 12.624 30.156 12.648 ;
     RECT  29.293 12.648 30.204 12.72 ;
     RECT  29.293 12.72 30.156 12.744 ;
     RECT  29.293 12.744 30.204 12.816 ;
     RECT  29.293 12.816 30.156 12.84 ;
     RECT  29.293 12.84 30.204 12.912 ;
     RECT  29.293 12.912 30.156 12.936 ;
    LAYER M5 ;
     RECT  23.016 0.016 23.088 0.084 ;
     RECT  23.112 0.016 23.184 0.084 ;
     RECT  23.208 0.016 23.28 0.084 ;
     RECT  23.304 0.016 23.376 0.084 ;
     RECT  23.4 0.016 23.472 0.084 ;
     RECT  23.496 0.016 23.568 0.084 ;
     RECT  23.592 0.016 23.664 0.084 ;
     RECT  23.688 0.016 23.76 0.084 ;
     RECT  23.784 0.016 23.856 0.084 ;
     RECT  23.88 0.016 23.952 0.084 ;
     RECT  23.976 0.016 24.048 0.084 ;
     RECT  24.072 0.016 24.144 0.084 ;
     RECT  24.168 0.016 24.24 0.084 ;
     RECT  24.264 0.016 24.336 0.084 ;
     RECT  24.36 0.016 24.432 0.084 ;
     RECT  24.456 0.016 24.528 0.084 ;
     RECT  24.552 0.016 24.624 0.084 ;
     RECT  24.648 0.016 24.72 0.084 ;
     RECT  24.744 0.016 24.816 0.084 ;
     RECT  24.84 0.016 24.912 0.084 ;
     RECT  24.936 0.016 25.008 0.084 ;
     RECT  25.032 0.016 25.104 0.084 ;
     RECT  25.128 0.016 25.2 0.084 ;
     RECT  25.224 0.016 25.296 0.084 ;
     RECT  25.32 0.016 25.392 0.084 ;
     RECT  25.416 0.016 25.488 0.084 ;
     RECT  25.512 0.016 25.584 0.084 ;
     RECT  25.608 0.016 25.68 0.084 ;
     RECT  25.704 0.016 25.776 0.084 ;
     RECT  25.8 0.016 25.872 0.084 ;
     RECT  25.896 0.016 25.968 0.084 ;
     RECT  25.992 0.016 26.064 0.084 ;
     RECT  26.088 0.016 26.16 0.084 ;
     RECT  26.184 0.016 26.256 0.084 ;
     RECT  26.28 0.016 26.352 0.084 ;
     RECT  26.376 0.016 26.448 0.084 ;
     RECT  26.472 0.016 26.544 0.084 ;
     RECT  26.568 0.016 26.64 0.084 ;
     RECT  26.664 0.016 26.736 0.084 ;
     RECT  26.76 0.016 26.832 0.084 ;
     RECT  26.856 0.016 26.928 0.084 ;
     RECT  26.952 0.016 27.024 0.084 ;
     RECT  27.048 0.016 27.12 0.084 ;
     RECT  27.144 0.016 27.216 0.084 ;
     RECT  27.24 0.016 27.312 0.084 ;
     RECT  27.336 0.016 27.408 0.084 ;
     RECT  27.432 0.016 27.504 0.084 ;
     RECT  27.528 0.016 27.6 0.084 ;
     RECT  27.624 0.016 27.696 0.084 ;
     RECT  27.72 0.016 27.792 0.084 ;
     RECT  27.816 0.016 27.888 0.084 ;
     RECT  27.912 0.016 27.984 0.084 ;
     RECT  28.008 0.016 28.08 0.084 ;
     RECT  28.104 0.016 28.176 0.084 ;
     RECT  28.2 0.016 28.272 0.084 ;
     RECT  28.296 0.016 28.368 0.084 ;
     RECT  28.392 0.016 28.464 0.084 ;
     RECT  28.488 0.016 28.56 0.084 ;
     RECT  28.584 0.016 28.656 0.084 ;
     RECT  28.68 0.016 28.752 0.084 ;
     RECT  28.776 0.016 28.848 0.084 ;
     RECT  28.872 0.016 28.944 0.084 ;
     RECT  28.968 0.016 29.04 0.084 ;
     RECT  22.992 0.084 29.064 0.131 ;
     RECT  22.992 0.131 28.968 0.179 ;
     RECT  19.944 0.016 20.016 0.084 ;
     RECT  20.04 0.016 20.112 0.084 ;
     RECT  20.136 0.016 20.208 0.084 ;
     RECT  19.92 0.084 20.232 0.611 ;
     RECT  22.992 0.179 28.392 0.803 ;
     RECT  23.088 0.803 28.392 1.139 ;
     RECT  19.92 0.611 20.136 1.187 ;
     RECT  23.088 1.139 27.336 1.715 ;
     RECT  21.888 0.421 21.912 2.137 ;
     RECT  2.4 2.137 2.52 2.151 ;
     RECT  5.1 2.137 5.22 2.151 ;
     RECT  7.8 2.137 7.92 2.151 ;
     RECT  10.5 2.137 10.62 2.151 ;
     RECT  13.2 2.137 13.32 2.151 ;
     RECT  15.9 2.137 16.02 2.151 ;
     RECT  18.6 2.137 18.72 2.151 ;
     RECT  28.368 1.139 28.392 2.339 ;
     RECT  24 1.715 27.336 2.387 ;
     RECT  15.9 2.151 16.212 2.389 ;
     RECT  21.3 2.137 21.912 2.389 ;
     RECT  7.8 2.151 8.112 2.533 ;
     RECT  19.92 1.187 19.944 2.629 ;
     RECT  21.168 2.389 21.912 2.629 ;
     RECT  19.92 2.629 21.912 2.773 ;
     RECT  19.92 2.773 22.776 2.869 ;
     RECT  24 2.387 27.24 2.869 ;
     RECT  7.152 2.533 8.112 3.443 ;
     RECT  19.92 2.869 27.24 3.443 ;
     RECT  20.88 3.443 27.24 3.875 ;
     RECT  15.696 2.389 16.212 4.115 ;
     RECT  21.3 3.875 27.24 4.163 ;
     RECT  13.2 2.151 13.512 4.501 ;
     RECT  2.4 2.151 2.712 5.029 ;
     RECT  17.52 4.453 17.544 5.171 ;
     RECT  21.3 4.163 27.012 5.221 ;
     RECT  10.5 2.151 10.812 5.749 ;
     RECT  21.168 5.221 27.012 5.749 ;
     RECT  5.1 2.151 5.412 5.845 ;
     RECT  20.448 5.749 27.012 6.037 ;
     RECT  2.304 5.029 2.712 6.803 ;
     RECT  13.008 4.501 13.512 6.851 ;
     RECT  4.56 5.845 5.412 6.899 ;
     RECT  10.08 5.749 10.812 7.379 ;
     RECT  29.328 7.525 29.352 7.717 ;
     RECT  5.1 6.899 5.412 7.957 ;
     RECT  20.064 6.037 27.012 8.435 ;
     RECT  17.568 5.605 17.592 8.533 ;
     RECT  18.6 2.151 18.912 8.533 ;
     RECT  20.064 8.435 24.312 8.579 ;
     RECT  10.368 7.379 10.812 8.821 ;
     RECT  13.2 6.851 13.512 8.821 ;
     RECT  14.784 7.429 14.808 9.011 ;
     RECT  29.328 7.717 30.12 9.061 ;
     RECT  17.568 8.533 18.912 9.155 ;
     RECT  20.064 8.579 22.92 9.203 ;
     RECT  10.368 8.821 11.256 9.299 ;
     RECT  15.9 4.115 16.212 9.397 ;
     RECT  17.568 9.155 17.592 9.397 ;
     RECT  15.9 9.397 17.592 9.443 ;
     RECT  4.56 7.957 5.412 9.491 ;
     RECT  20.064 9.203 22.776 9.539 ;
     RECT  25.488 8.435 27.012 9.635 ;
     RECT  26.592 9.635 27.012 9.637 ;
     RECT  25.488 9.635 25.512 9.731 ;
     RECT  10.5 9.299 11.256 9.827 ;
     RECT  13.104 8.821 13.512 9.923 ;
     RECT  26.592 9.637 27.624 10.309 ;
     RECT  28.752 9.061 30.12 10.309 ;
     RECT  21.3 9.539 22.776 10.453 ;
     RECT  24 8.579 24.312 10.453 ;
     RECT  21.3 10.453 24.312 10.597 ;
     RECT  26.592 10.309 30.12 10.597 ;
     RECT  21.12 10.597 24.312 11.363 ;
     RECT  22.752 11.363 24.312 11.365 ;
     RECT  26.064 10.597 30.12 11.365 ;
     RECT  18.6 9.155 18.912 11.413 ;
     RECT  20.064 9.539 20.088 11.413 ;
     RECT  22.752 11.365 24.408 11.459 ;
     RECT  18.6 11.413 20.088 11.797 ;
     RECT  21.12 11.363 21.612 11.797 ;
     RECT  13.2 9.923 13.512 11.941 ;
     RECT  23.04 11.459 24.408 11.989 ;
     RECT  25.632 11.365 30.12 11.989 ;
     RECT  18.6 11.797 21.612 12.515 ;
     RECT  15.9 9.443 17.16 12.517 ;
     RECT  13.2 11.941 13.704 12.755 ;
     RECT  15.9 12.517 17.4 12.803 ;
     RECT  5.1 9.491 5.412 12.901 ;
     RECT  3.744 9.637 3.768 13.091 ;
     RECT  20.688 12.515 21.612 13.093 ;
     RECT  2.4 6.803 2.712 13.429 ;
     RECT  23.04 11.989 30.12 13.667 ;
     RECT  20.688 13.093 21.864 14.099 ;
     RECT  2.4 13.429 2.808 14.243 ;
     RECT  14.784 10.069 14.808 14.485 ;
     RECT  15.9 12.803 16.212 14.485 ;
     RECT  10.5 9.827 10.812 14.821 ;
     RECT  17.376 12.803 17.4 14.867 ;
     RECT  20.688 14.099 21.72 14.867 ;
     RECT  13.2 12.755 13.512 14.965 ;
     RECT  14.784 14.485 16.212 14.965 ;
     RECT  13.2 14.965 16.212 15.205 ;
     RECT  10.5 14.821 11.208 15.491 ;
     RECT  25.632 13.667 30.12 16.019 ;
     RECT  25.632 16.019 25.656 16.307 ;
     RECT  13.2 15.205 16.344 16.357 ;
     RECT  13.056 16.357 16.392 16.403 ;
     RECT  7.8 3.443 8.112 16.501 ;
     RECT  30.096 16.019 30.12 16.595 ;
     RECT  26.7 16.019 28.776 16.643 ;
     RECT  23.04 13.667 24.312 16.885 ;
     RECT  7.2 16.501 8.112 17.077 ;
     RECT  22.992 16.885 24.312 17.077 ;
     RECT  26.7 16.643 27.816 17.123 ;
     RECT  7.2 17.077 9.096 17.171 ;
     RECT  15.9 16.403 16.392 17.171 ;
     RECT  7.68 17.171 9.096 17.219 ;
     RECT  22.608 17.077 24.312 17.699 ;
     RECT  4.896 12.901 5.412 17.989 ;
     RECT  24 17.699 24.312 17.989 ;
     RECT  25.488 17.077 25.512 17.989 ;
     RECT  24 17.989 25.512 18.035 ;
     RECT  2.4 14.243 2.712 18.181 ;
     RECT  20.688 14.867 21.612 18.181 ;
     RECT  22.608 17.699 22.632 18.181 ;
     RECT  4.896 17.989 5.736 18.565 ;
     RECT  13.056 16.403 14.808 18.659 ;
     RECT  20.688 18.181 22.632 19.237 ;
     RECT  24 18.035 24.552 19.237 ;
     RECT  20.688 19.237 24.552 19.283 ;
     RECT  13.2 18.659 14.808 19.285 ;
     RECT  15.9 17.171 16.344 19.285 ;
     RECT  2.304 18.181 2.712 19.571 ;
     RECT  7.68 17.219 8.112 19.811 ;
     RECT  13.2 19.285 16.344 20.003 ;
     RECT  3.936 18.565 5.736 20.579 ;
     RECT  20.688 19.283 24.312 20.675 ;
     RECT  18.6 12.515 18.912 20.725 ;
     RECT  26.7 17.123 27.012 21.013 ;
     RECT  10.5 15.491 11.016 21.061 ;
     RECT  3.936 20.579 5.412 21.683 ;
     RECT  15.408 20.003 16.344 21.685 ;
     RECT  18.6 20.725 19.368 21.973 ;
     RECT  17.904 21.973 19.368 22.019 ;
     RECT  2.4 19.571 2.712 22.021 ;
     RECT  10.5 21.061 11.448 22.261 ;
     RECT  10.5 22.261 11.976 22.307 ;
     RECT  15.408 21.685 16.872 22.307 ;
     RECT  3.936 21.683 3.96 23.029 ;
     RECT  5.1 21.683 5.412 23.029 ;
     RECT  11.952 22.307 11.976 23.411 ;
     RECT  15.408 22.307 16.212 23.605 ;
     RECT  15.408 23.605 16.44 23.651 ;
     RECT  2.304 22.021 2.712 23.891 ;
     RECT  13.2 20.003 14.184 23.893 ;
     RECT  15.9 23.651 16.44 23.893 ;
     RECT  17.904 22.019 18.912 23.941 ;
     RECT  17.568 23.941 18.912 24.323 ;
     RECT  2.4 23.891 2.712 24.469 ;
     RECT  3.936 23.029 5.412 24.611 ;
     RECT  20.688 20.675 22.536 24.755 ;
     RECT  15.9 23.893 16.536 24.901 ;
     RECT  13.2 23.893 14.328 24.997 ;
     RECT  15.36 24.901 16.536 24.997 ;
     RECT  2.4 24.469 2.856 25.045 ;
     RECT  10.5 22.307 10.812 25.045 ;
     RECT  10.5 25.045 10.92 25.475 ;
     RECT  3.936 24.611 3.96 25.715 ;
     RECT  20.688 24.755 21.612 25.715 ;
     RECT  26.592 21.013 27.012 25.715 ;
     RECT  2.4 25.045 2.952 25.763 ;
     RECT  13.2 24.997 16.536 26.101 ;
     RECT  17.712 24.323 18.912 26.101 ;
     RECT  13.2 26.101 18.912 26.579 ;
     RECT  13.2 26.579 14.328 26.629 ;
     RECT  12.48 26.629 14.328 26.819 ;
     RECT  15.312 26.579 18.912 26.819 ;
     RECT  2.4 25.763 2.712 27.349 ;
     RECT  12.48 26.819 14.184 27.395 ;
     RECT  2.4 27.349 2.904 27.923 ;
     RECT  13.2 27.395 14.184 27.925 ;
     RECT  15.312 26.819 17.16 27.925 ;
     RECT  18.6 26.819 18.912 27.925 ;
     RECT  2.4 27.923 2.712 28.089 ;
     RECT  5.1 24.611 5.412 28.089 ;
     RECT  7.8 19.811 8.112 28.089 ;
     RECT  10.5 25.475 10.812 28.089 ;
     RECT  21.3 25.715 21.612 28.089 ;
     RECT  24 20.675 24.312 28.089 ;
     RECT  26.7 25.715 27.012 28.089 ;
     RECT  2.4 28.089 2.52 28.103 ;
     RECT  5.1 28.089 5.22 28.103 ;
     RECT  7.8 28.089 7.92 28.103 ;
     RECT  10.5 28.089 10.62 28.103 ;
     RECT  13.2 27.925 17.16 28.103 ;
     RECT  18.6 27.925 19.944 28.103 ;
     RECT  21.3 28.089 21.42 28.103 ;
     RECT  24 28.089 24.12 28.103 ;
     RECT  26.7 28.089 26.82 28.103 ;
     RECT  19.536 28.103 19.944 28.405 ;
     RECT  19.536 28.405 20.136 28.453 ;
     RECT  14.16 28.103 17.16 30.156 ;
     RECT  14.184 30.156 14.256 30.224 ;
     RECT  14.28 30.156 14.352 30.224 ;
     RECT  14.376 30.156 14.448 30.224 ;
     RECT  14.472 30.156 14.544 30.224 ;
     RECT  14.568 30.156 14.64 30.224 ;
     RECT  14.664 30.156 14.736 30.224 ;
     RECT  14.76 30.156 14.832 30.224 ;
     RECT  14.856 30.156 14.928 30.224 ;
     RECT  14.952 30.156 15.024 30.224 ;
     RECT  15.048 30.156 15.12 30.224 ;
     RECT  15.144 30.156 15.216 30.224 ;
     RECT  15.24 30.156 15.312 30.224 ;
     RECT  15.336 30.156 15.408 30.224 ;
     RECT  15.432 30.156 15.504 30.224 ;
     RECT  15.528 30.156 15.6 30.224 ;
     RECT  15.624 30.156 15.696 30.224 ;
     RECT  15.72 30.156 15.792 30.224 ;
     RECT  15.816 30.156 15.888 30.224 ;
     RECT  15.912 30.156 15.984 30.224 ;
     RECT  16.008 30.156 16.08 30.224 ;
     RECT  16.104 30.156 16.176 30.224 ;
     RECT  16.2 30.156 16.272 30.224 ;
     RECT  16.296 30.156 16.368 30.224 ;
     RECT  16.392 30.156 16.464 30.224 ;
     RECT  16.488 30.156 16.56 30.224 ;
     RECT  16.584 30.156 16.656 30.224 ;
     RECT  16.68 30.156 16.752 30.224 ;
     RECT  16.776 30.156 16.848 30.224 ;
     RECT  16.872 30.156 16.944 30.224 ;
     RECT  16.968 30.156 17.04 30.224 ;
     RECT  17.064 30.156 17.136 30.224 ;
     RECT  19.536 28.453 20.232 30.156 ;
     RECT  19.56 30.156 19.632 30.224 ;
     RECT  19.656 30.156 19.728 30.224 ;
     RECT  19.752 30.156 19.824 30.224 ;
     RECT  19.848 30.156 19.92 30.224 ;
     RECT  19.944 30.156 20.016 30.224 ;
     RECT  20.04 30.156 20.112 30.224 ;
     RECT  20.136 30.156 20.208 30.224 ;
     RECT  21.912 0.421 22.992 0.803 ;
     RECT  20.136 0.611 20.232 1.187 ;
     RECT  21.912 0.803 23.088 1.715 ;
     RECT  27.336 1.139 28.368 2.339 ;
     RECT  19.944 1.187 20.232 2.137 ;
     RECT  21.912 1.715 24 2.773 ;
     RECT  18.72 2.137 19.92 2.151 ;
     RECT  19.944 2.137 21.3 2.389 ;
     RECT  18.912 2.151 19.92 3.443 ;
     RECT  19.944 2.389 21.168 2.629 ;
     RECT  22.776 2.773 24 2.869 ;
     RECT  21.168 3.875 21.3 5.221 ;
     RECT  16.212 4.453 17.52 5.171 ;
     RECT  17.544 4.453 18.6 5.171 ;
     RECT  16.212 5.171 18.6 5.605 ;
     RECT  16.212 5.605 17.568 9.397 ;
     RECT  17.592 5.605 18.6 8.533 ;
     RECT  18.912 6.037 20.064 11.413 ;
     RECT  4.56 6.899 5.1 7.957 ;
     RECT  13.512 7.429 14.784 9.011 ;
     RECT  14.808 7.429 15.9 9.011 ;
     RECT  24.312 8.435 25.488 9.731 ;
     RECT  22.92 8.579 24 9.203 ;
     RECT  13.512 9.011 15.9 10.069 ;
     RECT  17.592 9.155 18.6 9.443 ;
     RECT  22.776 9.203 24 10.453 ;
     RECT  17.16 9.443 18.6 12.517 ;
     RECT  4.56 9.491 5.1 9.637 ;
     RECT  20.088 9.539 21.3 10.597 ;
     RECT  25.512 9.635 26.592 9.731 ;
     RECT  2.712 9.637 3.744 13.091 ;
     RECT  3.768 9.637 5.1 12.901 ;
     RECT  27.624 9.637 28.752 10.309 ;
     RECT  26.064 9.731 26.592 10.597 ;
     RECT  13.512 10.069 14.784 11.941 ;
     RECT  14.808 10.069 15.9 14.485 ;
     RECT  20.088 10.597 21.12 11.797 ;
     RECT  21.612 11.363 22.752 11.459 ;
     RECT  24.408 11.365 25.632 11.989 ;
     RECT  21.612 11.459 23.04 13.093 ;
     RECT  13.704 11.941 14.784 12.755 ;
     RECT  17.4 12.517 18.6 14.867 ;
     RECT  13.512 12.755 14.784 14.965 ;
     RECT  16.212 12.803 17.376 14.867 ;
     RECT  3.768 12.901 4.896 13.091 ;
     RECT  2.712 13.091 2.808 13.429 ;
     RECT  21.864 13.093 23.04 14.099 ;
     RECT  24.312 13.667 25.632 16.307 ;
     RECT  21.72 14.099 23.04 14.867 ;
     RECT  16.212 14.867 16.392 15.205 ;
     RECT  21.612 14.867 23.04 16.885 ;
     RECT  16.344 15.205 16.392 16.357 ;
     RECT  25.656 16.019 26.7 16.307 ;
     RECT  28.776 16.019 30.096 16.595 ;
     RECT  24.312 16.307 26.7 17.077 ;
     RECT  14.808 16.403 15.9 19.285 ;
     RECT  21.612 16.885 22.992 17.077 ;
     RECT  9.096 17.077 10.5 17.219 ;
     RECT  21.612 17.077 22.608 18.181 ;
     RECT  24.312 17.077 25.488 17.989 ;
     RECT  25.512 17.077 26.7 18.035 ;
     RECT  22.632 17.699 24 19.237 ;
     RECT  2.712 18.565 3.936 24.469 ;
     RECT  14.184 20.003 15.408 23.651 ;
     RECT  22.536 20.675 24 24.755 ;
     RECT  19.368 20.725 20.688 22.019 ;
     RECT  3.96 21.683 5.1 23.029 ;
     RECT  16.872 21.973 17.904 22.307 ;
     RECT  11.976 22.261 13.2 23.411 ;
     RECT  10.812 22.307 11.952 23.411 ;
     RECT  16.212 22.307 17.904 23.605 ;
     RECT  16.44 23.605 17.904 23.893 ;
     RECT  14.184 23.651 15.9 23.893 ;
     RECT  14.328 23.893 15.9 24.901 ;
     RECT  16.536 23.893 17.904 23.941 ;
     RECT  16.536 23.941 17.568 24.323 ;
     RECT  16.536 24.323 17.712 26.101 ;
     RECT  2.856 24.469 3.936 25.045 ;
     RECT  3.96 24.611 5.1 25.715 ;
     RECT  14.328 24.901 15.36 24.997 ;
     RECT  2.952 25.045 3.936 25.715 ;
     RECT  14.328 26.579 15.312 26.819 ;
     RECT  14.184 26.819 15.312 27.925 ;
     RECT  17.16 26.819 18.6 28.103 ;
     RECT  19.944 27.925 21.3 28.103 ;
     RECT  19.944 28.103 20.232 28.405 ;
     RECT  20.136 28.405 20.232 28.453 ;
  END
END qkd_kv_landing_cal
END LIBRARY
